VERSION 5.7 ;
  NOWIREEXTENSIONATPIN ON ;
  DIVIDERCHAR "/" ;
  BUSBITCHARS "[]" ;
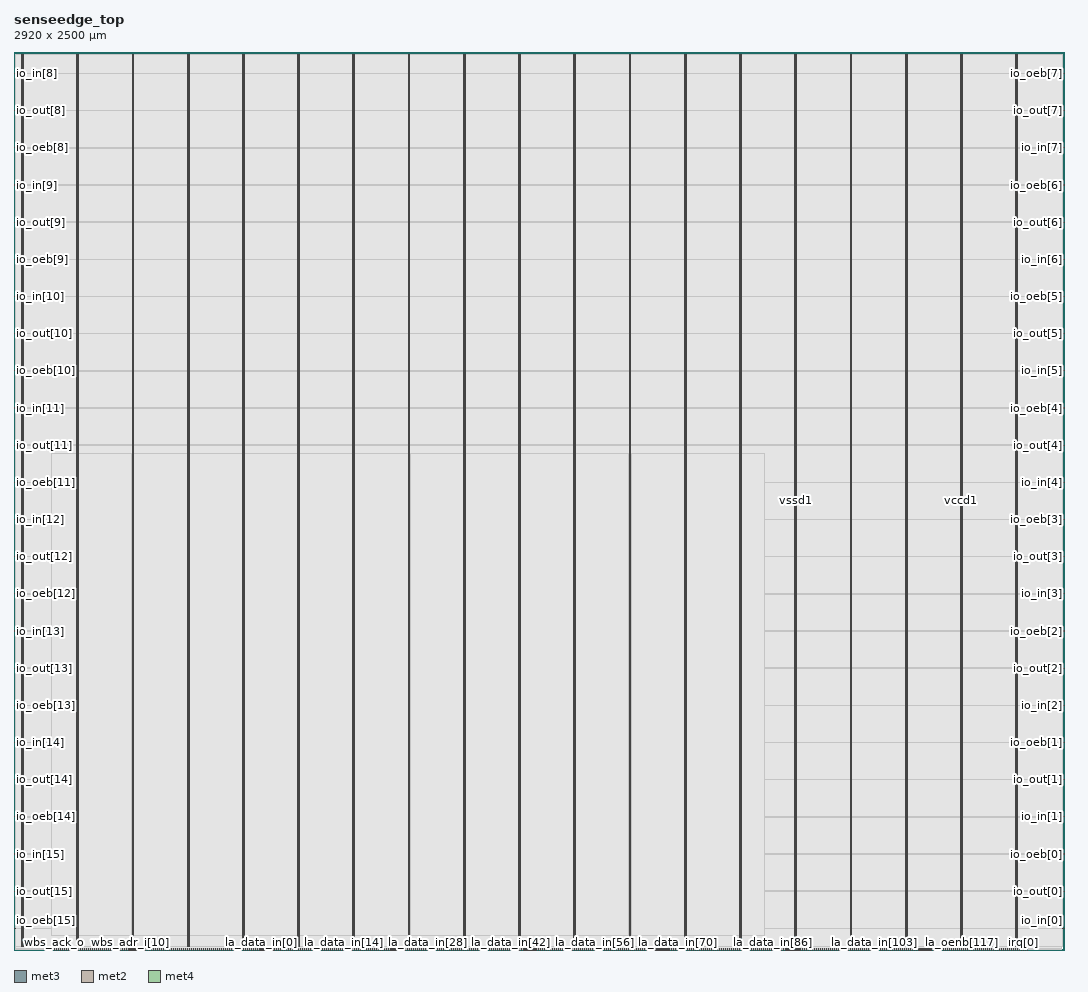
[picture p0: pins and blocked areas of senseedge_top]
MACRO senseedge_top
  CLASS BLOCK ;
  FOREIGN senseedge_top ;
  ORIGIN 0.000 0.000 ;
  SIZE 2920.000 BY 2500.000 ;
  PIN io_in[0]
    DIRECTION INPUT ;
    USE SIGNAL ;
    ANTENNAGATEAREA 1.424700 ;
    ANTENNADIFFAREA 0.434700 ;
    PORT
      LAYER met3 ;
        RECT 2916.000 59.880 2920.000 60.480 ;
    END
  END io_in[0]
  PIN io_in[10]
    DIRECTION INPUT ;
    USE SIGNAL ;
    PORT
      LAYER met3 ;
        RECT 0.000 1817.000 4.000 1817.600 ;
    END
  END io_in[10]
  PIN io_in[11]
    DIRECTION INPUT ;
    USE SIGNAL ;
    PORT
      LAYER met3 ;
        RECT 0.000 1506.920 4.000 1507.520 ;
    END
  END io_in[11]
  PIN io_in[12]
    DIRECTION INPUT ;
    USE SIGNAL ;
    PORT
      LAYER met3 ;
        RECT 0.000 1196.840 4.000 1197.440 ;
    END
  END io_in[12]
  PIN io_in[13]
    DIRECTION INPUT ;
    USE SIGNAL ;
    PORT
      LAYER met3 ;
        RECT 0.000 886.760 4.000 887.360 ;
    END
  END io_in[13]
  PIN io_in[14]
    DIRECTION INPUT ;
    USE SIGNAL ;
    PORT
      LAYER met3 ;
        RECT 0.000 576.680 4.000 577.280 ;
    END
  END io_in[14]
  PIN io_in[15]
    DIRECTION INPUT ;
    USE SIGNAL ;
    PORT
      LAYER met3 ;
        RECT 0.000 266.600 4.000 267.200 ;
    END
  END io_in[15]
  PIN io_in[1]
    DIRECTION INPUT ;
    USE SIGNAL ;
    PORT
      LAYER met3 ;
        RECT 2916.000 369.960 2920.000 370.560 ;
    END
  END io_in[1]
  PIN io_in[2]
    DIRECTION INPUT ;
    USE SIGNAL ;
    PORT
      LAYER met3 ;
        RECT 2916.000 680.040 2920.000 680.640 ;
    END
  END io_in[2]
  PIN io_in[3]
    DIRECTION INPUT ;
    USE SIGNAL ;
    PORT
      LAYER met3 ;
        RECT 2916.000 990.120 2920.000 990.720 ;
    END
  END io_in[3]
  PIN io_in[4]
    DIRECTION INPUT ;
    USE SIGNAL ;
    PORT
      LAYER met3 ;
        RECT 2916.000 1300.200 2920.000 1300.800 ;
    END
  END io_in[4]
  PIN io_in[5]
    DIRECTION INPUT ;
    USE SIGNAL ;
    PORT
      LAYER met3 ;
        RECT 2916.000 1610.280 2920.000 1610.880 ;
    END
  END io_in[5]
  PIN io_in[6]
    DIRECTION INPUT ;
    USE SIGNAL ;
    PORT
      LAYER met3 ;
        RECT 2916.000 1920.360 2920.000 1920.960 ;
    END
  END io_in[6]
  PIN io_in[7]
    DIRECTION INPUT ;
    USE SIGNAL ;
    PORT
      LAYER met3 ;
        RECT 2916.000 2230.440 2920.000 2231.040 ;
    END
  END io_in[7]
  PIN io_in[8]
    DIRECTION INPUT ;
    USE SIGNAL ;
    PORT
      LAYER met3 ;
        RECT 0.000 2437.160 4.000 2437.760 ;
    END
  END io_in[8]
  PIN io_in[9]
    DIRECTION INPUT ;
    USE SIGNAL ;
    PORT
      LAYER met3 ;
        RECT 0.000 2127.080 4.000 2127.680 ;
    END
  END io_in[9]
  PIN io_oeb[0]
    DIRECTION OUTPUT ;
    USE SIGNAL ;
    PORT
      LAYER met3 ;
        RECT 2916.000 266.600 2920.000 267.200 ;
    END
  END io_oeb[0]
  PIN io_oeb[10]
    DIRECTION OUTPUT ;
    USE SIGNAL ;
    PORT
      LAYER met3 ;
        RECT 0.000 1610.280 4.000 1610.880 ;
    END
  END io_oeb[10]
  PIN io_oeb[11]
    DIRECTION OUTPUT ;
    USE SIGNAL ;
    PORT
      LAYER met3 ;
        RECT 0.000 1300.200 4.000 1300.800 ;
    END
  END io_oeb[11]
  PIN io_oeb[12]
    DIRECTION OUTPUT ;
    USE SIGNAL ;
    PORT
      LAYER met3 ;
        RECT 0.000 990.120 4.000 990.720 ;
    END
  END io_oeb[12]
  PIN io_oeb[13]
    DIRECTION OUTPUT ;
    USE SIGNAL ;
    PORT
      LAYER met3 ;
        RECT 0.000 680.040 4.000 680.640 ;
    END
  END io_oeb[13]
  PIN io_oeb[14]
    DIRECTION OUTPUT ;
    USE SIGNAL ;
    PORT
      LAYER met3 ;
        RECT 0.000 369.960 4.000 370.560 ;
    END
  END io_oeb[14]
  PIN io_oeb[15]
    DIRECTION OUTPUT ;
    USE SIGNAL ;
    PORT
      LAYER met3 ;
        RECT 0.000 59.880 4.000 60.480 ;
    END
  END io_oeb[15]
  PIN io_oeb[1]
    DIRECTION OUTPUT ;
    USE SIGNAL ;
    PORT
      LAYER met3 ;
        RECT 2916.000 576.680 2920.000 577.280 ;
    END
  END io_oeb[1]
  PIN io_oeb[2]
    DIRECTION OUTPUT ;
    USE SIGNAL ;
    PORT
      LAYER met3 ;
        RECT 2916.000 886.760 2920.000 887.360 ;
    END
  END io_oeb[2]
  PIN io_oeb[3]
    DIRECTION OUTPUT ;
    USE SIGNAL ;
    PORT
      LAYER met3 ;
        RECT 2916.000 1196.840 2920.000 1197.440 ;
    END
  END io_oeb[3]
  PIN io_oeb[4]
    DIRECTION OUTPUT ;
    USE SIGNAL ;
    PORT
      LAYER met3 ;
        RECT 2916.000 1506.920 2920.000 1507.520 ;
    END
  END io_oeb[4]
  PIN io_oeb[5]
    DIRECTION OUTPUT ;
    USE SIGNAL ;
    PORT
      LAYER met3 ;
        RECT 2916.000 1817.000 2920.000 1817.600 ;
    END
  END io_oeb[5]
  PIN io_oeb[6]
    DIRECTION OUTPUT ;
    USE SIGNAL ;
    PORT
      LAYER met3 ;
        RECT 2916.000 2127.080 2920.000 2127.680 ;
    END
  END io_oeb[6]
  PIN io_oeb[7]
    DIRECTION OUTPUT ;
    USE SIGNAL ;
    PORT
      LAYER met3 ;
        RECT 2916.000 2437.160 2920.000 2437.760 ;
    END
  END io_oeb[7]
  PIN io_oeb[8]
    DIRECTION OUTPUT ;
    USE SIGNAL ;
    PORT
      LAYER met3 ;
        RECT 0.000 2230.440 4.000 2231.040 ;
    END
  END io_oeb[8]
  PIN io_oeb[9]
    DIRECTION OUTPUT ;
    USE SIGNAL ;
    PORT
      LAYER met3 ;
        RECT 0.000 1920.360 4.000 1920.960 ;
    END
  END io_oeb[9]
  PIN io_out[0]
    DIRECTION OUTPUT ;
    USE SIGNAL ;
    PORT
      LAYER met3 ;
        RECT 2916.000 163.240 2920.000 163.840 ;
    END
  END io_out[0]
  PIN io_out[10]
    DIRECTION OUTPUT ;
    USE SIGNAL ;
    PORT
      LAYER met3 ;
        RECT 0.000 1713.640 4.000 1714.240 ;
    END
  END io_out[10]
  PIN io_out[11]
    DIRECTION OUTPUT ;
    USE SIGNAL ;
    PORT
      LAYER met3 ;
        RECT 0.000 1403.560 4.000 1404.160 ;
    END
  END io_out[11]
  PIN io_out[12]
    DIRECTION OUTPUT ;
    USE SIGNAL ;
    PORT
      LAYER met3 ;
        RECT 0.000 1093.480 4.000 1094.080 ;
    END
  END io_out[12]
  PIN io_out[13]
    DIRECTION OUTPUT ;
    USE SIGNAL ;
    PORT
      LAYER met3 ;
        RECT 0.000 783.400 4.000 784.000 ;
    END
  END io_out[13]
  PIN io_out[14]
    DIRECTION OUTPUT ;
    USE SIGNAL ;
    PORT
      LAYER met3 ;
        RECT 0.000 473.320 4.000 473.920 ;
    END
  END io_out[14]
  PIN io_out[15]
    DIRECTION OUTPUT ;
    USE SIGNAL ;
    PORT
      LAYER met3 ;
        RECT 0.000 163.240 4.000 163.840 ;
    END
  END io_out[15]
  PIN io_out[1]
    DIRECTION OUTPUT ;
    USE SIGNAL ;
    ANTENNADIFFAREA 2.673000 ;
    PORT
      LAYER met3 ;
        RECT 2916.000 473.320 2920.000 473.920 ;
    END
  END io_out[1]
  PIN io_out[2]
    DIRECTION OUTPUT ;
    USE SIGNAL ;
    ANTENNADIFFAREA 2.673000 ;
    PORT
      LAYER met3 ;
        RECT 2916.000 783.400 2920.000 784.000 ;
    END
  END io_out[2]
  PIN io_out[3]
    DIRECTION OUTPUT ;
    USE SIGNAL ;
    ANTENNADIFFAREA 2.673000 ;
    PORT
      LAYER met3 ;
        RECT 2916.000 1093.480 2920.000 1094.080 ;
    END
  END io_out[3]
  PIN io_out[4]
    DIRECTION OUTPUT ;
    USE SIGNAL ;
    ANTENNADIFFAREA 2.673000 ;
    PORT
      LAYER met3 ;
        RECT 2916.000 1403.560 2920.000 1404.160 ;
    END
  END io_out[4]
  PIN io_out[5]
    DIRECTION OUTPUT ;
    USE SIGNAL ;
    PORT
      LAYER met3 ;
        RECT 2916.000 1713.640 2920.000 1714.240 ;
    END
  END io_out[5]
  PIN io_out[6]
    DIRECTION OUTPUT ;
    USE SIGNAL ;
    PORT
      LAYER met3 ;
        RECT 2916.000 2023.720 2920.000 2024.320 ;
    END
  END io_out[6]
  PIN io_out[7]
    DIRECTION OUTPUT ;
    USE SIGNAL ;
    PORT
      LAYER met3 ;
        RECT 2916.000 2333.800 2920.000 2334.400 ;
    END
  END io_out[7]
  PIN io_out[8]
    DIRECTION OUTPUT ;
    USE SIGNAL ;
    PORT
      LAYER met3 ;
        RECT 0.000 2333.800 4.000 2334.400 ;
    END
  END io_out[8]
  PIN io_out[9]
    DIRECTION OUTPUT ;
    USE SIGNAL ;
    PORT
      LAYER met3 ;
        RECT 0.000 2023.720 4.000 2024.320 ;
    END
  END io_out[9]
  PIN irq[0]
    DIRECTION OUTPUT ;
    USE SIGNAL ;
    ANTENNADIFFAREA 2.673000 ;
    PORT
      LAYER met2 ;
        RECT 2806.550 0.000 2806.830 4.000 ;
    END
  END irq[0]
  PIN irq[1]
    DIRECTION OUTPUT ;
    USE SIGNAL ;
    PORT
      LAYER met2 ;
        RECT 2812.070 0.000 2812.350 4.000 ;
    END
  END irq[1]
  PIN irq[2]
    DIRECTION OUTPUT ;
    USE SIGNAL ;
    PORT
      LAYER met2 ;
        RECT 2817.590 0.000 2817.870 4.000 ;
    END
  END irq[2]
  PIN la_data_in[0]
    DIRECTION INPUT ;
    USE SIGNAL ;
    PORT
      LAYER met2 ;
        RECT 686.870 0.000 687.150 4.000 ;
    END
  END la_data_in[0]
  PIN la_data_in[100]
    DIRECTION INPUT ;
    USE SIGNAL ;
    PORT
      LAYER met2 ;
        RECT 2342.870 0.000 2343.150 4.000 ;
    END
  END la_data_in[100]
  PIN la_data_in[101]
    DIRECTION INPUT ;
    USE SIGNAL ;
    PORT
      LAYER met2 ;
        RECT 2359.430 0.000 2359.710 4.000 ;
    END
  END la_data_in[101]
  PIN la_data_in[102]
    DIRECTION INPUT ;
    USE SIGNAL ;
    PORT
      LAYER met2 ;
        RECT 2375.990 0.000 2376.270 4.000 ;
    END
  END la_data_in[102]
  PIN la_data_in[103]
    DIRECTION INPUT ;
    USE SIGNAL ;
    PORT
      LAYER met2 ;
        RECT 2392.550 0.000 2392.830 4.000 ;
    END
  END la_data_in[103]
  PIN la_data_in[104]
    DIRECTION INPUT ;
    USE SIGNAL ;
    PORT
      LAYER met2 ;
        RECT 2409.110 0.000 2409.390 4.000 ;
    END
  END la_data_in[104]
  PIN la_data_in[105]
    DIRECTION INPUT ;
    USE SIGNAL ;
    PORT
      LAYER met2 ;
        RECT 2425.670 0.000 2425.950 4.000 ;
    END
  END la_data_in[105]
  PIN la_data_in[106]
    DIRECTION INPUT ;
    USE SIGNAL ;
    PORT
      LAYER met2 ;
        RECT 2442.230 0.000 2442.510 4.000 ;
    END
  END la_data_in[106]
  PIN la_data_in[107]
    DIRECTION INPUT ;
    USE SIGNAL ;
    PORT
      LAYER met2 ;
        RECT 2458.790 0.000 2459.070 4.000 ;
    END
  END la_data_in[107]
  PIN la_data_in[108]
    DIRECTION INPUT ;
    USE SIGNAL ;
    PORT
      LAYER met2 ;
        RECT 2475.350 0.000 2475.630 4.000 ;
    END
  END la_data_in[108]
  PIN la_data_in[109]
    DIRECTION INPUT ;
    USE SIGNAL ;
    PORT
      LAYER met2 ;
        RECT 2491.910 0.000 2492.190 4.000 ;
    END
  END la_data_in[109]
  PIN la_data_in[10]
    DIRECTION INPUT ;
    USE SIGNAL ;
    PORT
      LAYER met2 ;
        RECT 852.470 0.000 852.750 4.000 ;
    END
  END la_data_in[10]
  PIN la_data_in[110]
    DIRECTION INPUT ;
    USE SIGNAL ;
    PORT
      LAYER met2 ;
        RECT 2508.470 0.000 2508.750 4.000 ;
    END
  END la_data_in[110]
  PIN la_data_in[111]
    DIRECTION INPUT ;
    USE SIGNAL ;
    PORT
      LAYER met2 ;
        RECT 2525.030 0.000 2525.310 4.000 ;
    END
  END la_data_in[111]
  PIN la_data_in[112]
    DIRECTION INPUT ;
    USE SIGNAL ;
    PORT
      LAYER met2 ;
        RECT 2541.590 0.000 2541.870 4.000 ;
    END
  END la_data_in[112]
  PIN la_data_in[113]
    DIRECTION INPUT ;
    USE SIGNAL ;
    PORT
      LAYER met2 ;
        RECT 2558.150 0.000 2558.430 4.000 ;
    END
  END la_data_in[113]
  PIN la_data_in[114]
    DIRECTION INPUT ;
    USE SIGNAL ;
    PORT
      LAYER met2 ;
        RECT 2574.710 0.000 2574.990 4.000 ;
    END
  END la_data_in[114]
  PIN la_data_in[115]
    DIRECTION INPUT ;
    USE SIGNAL ;
    PORT
      LAYER met2 ;
        RECT 2591.270 0.000 2591.550 4.000 ;
    END
  END la_data_in[115]
  PIN la_data_in[116]
    DIRECTION INPUT ;
    USE SIGNAL ;
    PORT
      LAYER met2 ;
        RECT 2607.830 0.000 2608.110 4.000 ;
    END
  END la_data_in[116]
  PIN la_data_in[117]
    DIRECTION INPUT ;
    USE SIGNAL ;
    PORT
      LAYER met2 ;
        RECT 2624.390 0.000 2624.670 4.000 ;
    END
  END la_data_in[117]
  PIN la_data_in[118]
    DIRECTION INPUT ;
    USE SIGNAL ;
    PORT
      LAYER met2 ;
        RECT 2640.950 0.000 2641.230 4.000 ;
    END
  END la_data_in[118]
  PIN la_data_in[119]
    DIRECTION INPUT ;
    USE SIGNAL ;
    PORT
      LAYER met2 ;
        RECT 2657.510 0.000 2657.790 4.000 ;
    END
  END la_data_in[119]
  PIN la_data_in[11]
    DIRECTION INPUT ;
    USE SIGNAL ;
    PORT
      LAYER met2 ;
        RECT 869.030 0.000 869.310 4.000 ;
    END
  END la_data_in[11]
  PIN la_data_in[120]
    DIRECTION INPUT ;
    USE SIGNAL ;
    PORT
      LAYER met2 ;
        RECT 2674.070 0.000 2674.350 4.000 ;
    END
  END la_data_in[120]
  PIN la_data_in[121]
    DIRECTION INPUT ;
    USE SIGNAL ;
    PORT
      LAYER met2 ;
        RECT 2690.630 0.000 2690.910 4.000 ;
    END
  END la_data_in[121]
  PIN la_data_in[122]
    DIRECTION INPUT ;
    USE SIGNAL ;
    PORT
      LAYER met2 ;
        RECT 2707.190 0.000 2707.470 4.000 ;
    END
  END la_data_in[122]
  PIN la_data_in[123]
    DIRECTION INPUT ;
    USE SIGNAL ;
    PORT
      LAYER met2 ;
        RECT 2723.750 0.000 2724.030 4.000 ;
    END
  END la_data_in[123]
  PIN la_data_in[124]
    DIRECTION INPUT ;
    USE SIGNAL ;
    PORT
      LAYER met2 ;
        RECT 2740.310 0.000 2740.590 4.000 ;
    END
  END la_data_in[124]
  PIN la_data_in[125]
    DIRECTION INPUT ;
    USE SIGNAL ;
    PORT
      LAYER met2 ;
        RECT 2756.870 0.000 2757.150 4.000 ;
    END
  END la_data_in[125]
  PIN la_data_in[126]
    DIRECTION INPUT ;
    USE SIGNAL ;
    PORT
      LAYER met2 ;
        RECT 2773.430 0.000 2773.710 4.000 ;
    END
  END la_data_in[126]
  PIN la_data_in[127]
    DIRECTION INPUT ;
    USE SIGNAL ;
    PORT
      LAYER met2 ;
        RECT 2789.990 0.000 2790.270 4.000 ;
    END
  END la_data_in[127]
  PIN la_data_in[12]
    DIRECTION INPUT ;
    USE SIGNAL ;
    PORT
      LAYER met2 ;
        RECT 885.590 0.000 885.870 4.000 ;
    END
  END la_data_in[12]
  PIN la_data_in[13]
    DIRECTION INPUT ;
    USE SIGNAL ;
    PORT
      LAYER met2 ;
        RECT 902.150 0.000 902.430 4.000 ;
    END
  END la_data_in[13]
  PIN la_data_in[14]
    DIRECTION INPUT ;
    USE SIGNAL ;
    PORT
      LAYER met2 ;
        RECT 918.710 0.000 918.990 4.000 ;
    END
  END la_data_in[14]
  PIN la_data_in[15]
    DIRECTION INPUT ;
    USE SIGNAL ;
    PORT
      LAYER met2 ;
        RECT 935.270 0.000 935.550 4.000 ;
    END
  END la_data_in[15]
  PIN la_data_in[16]
    DIRECTION INPUT ;
    USE SIGNAL ;
    PORT
      LAYER met2 ;
        RECT 951.830 0.000 952.110 4.000 ;
    END
  END la_data_in[16]
  PIN la_data_in[17]
    DIRECTION INPUT ;
    USE SIGNAL ;
    PORT
      LAYER met2 ;
        RECT 968.390 0.000 968.670 4.000 ;
    END
  END la_data_in[17]
  PIN la_data_in[18]
    DIRECTION INPUT ;
    USE SIGNAL ;
    PORT
      LAYER met2 ;
        RECT 984.950 0.000 985.230 4.000 ;
    END
  END la_data_in[18]
  PIN la_data_in[19]
    DIRECTION INPUT ;
    USE SIGNAL ;
    PORT
      LAYER met2 ;
        RECT 1001.510 0.000 1001.790 4.000 ;
    END
  END la_data_in[19]
  PIN la_data_in[1]
    DIRECTION INPUT ;
    USE SIGNAL ;
    PORT
      LAYER met2 ;
        RECT 703.430 0.000 703.710 4.000 ;
    END
  END la_data_in[1]
  PIN la_data_in[20]
    DIRECTION INPUT ;
    USE SIGNAL ;
    PORT
      LAYER met2 ;
        RECT 1018.070 0.000 1018.350 4.000 ;
    END
  END la_data_in[20]
  PIN la_data_in[21]
    DIRECTION INPUT ;
    USE SIGNAL ;
    PORT
      LAYER met2 ;
        RECT 1034.630 0.000 1034.910 4.000 ;
    END
  END la_data_in[21]
  PIN la_data_in[22]
    DIRECTION INPUT ;
    USE SIGNAL ;
    PORT
      LAYER met2 ;
        RECT 1051.190 0.000 1051.470 4.000 ;
    END
  END la_data_in[22]
  PIN la_data_in[23]
    DIRECTION INPUT ;
    USE SIGNAL ;
    PORT
      LAYER met2 ;
        RECT 1067.750 0.000 1068.030 4.000 ;
    END
  END la_data_in[23]
  PIN la_data_in[24]
    DIRECTION INPUT ;
    USE SIGNAL ;
    PORT
      LAYER met2 ;
        RECT 1084.310 0.000 1084.590 4.000 ;
    END
  END la_data_in[24]
  PIN la_data_in[25]
    DIRECTION INPUT ;
    USE SIGNAL ;
    PORT
      LAYER met2 ;
        RECT 1100.870 0.000 1101.150 4.000 ;
    END
  END la_data_in[25]
  PIN la_data_in[26]
    DIRECTION INPUT ;
    USE SIGNAL ;
    PORT
      LAYER met2 ;
        RECT 1117.430 0.000 1117.710 4.000 ;
    END
  END la_data_in[26]
  PIN la_data_in[27]
    DIRECTION INPUT ;
    USE SIGNAL ;
    PORT
      LAYER met2 ;
        RECT 1133.990 0.000 1134.270 4.000 ;
    END
  END la_data_in[27]
  PIN la_data_in[28]
    DIRECTION INPUT ;
    USE SIGNAL ;
    PORT
      LAYER met2 ;
        RECT 1150.550 0.000 1150.830 4.000 ;
    END
  END la_data_in[28]
  PIN la_data_in[29]
    DIRECTION INPUT ;
    USE SIGNAL ;
    PORT
      LAYER met2 ;
        RECT 1167.110 0.000 1167.390 4.000 ;
    END
  END la_data_in[29]
  PIN la_data_in[2]
    DIRECTION INPUT ;
    USE SIGNAL ;
    PORT
      LAYER met2 ;
        RECT 719.990 0.000 720.270 4.000 ;
    END
  END la_data_in[2]
  PIN la_data_in[30]
    DIRECTION INPUT ;
    USE SIGNAL ;
    PORT
      LAYER met2 ;
        RECT 1183.670 0.000 1183.950 4.000 ;
    END
  END la_data_in[30]
  PIN la_data_in[31]
    DIRECTION INPUT ;
    USE SIGNAL ;
    PORT
      LAYER met2 ;
        RECT 1200.230 0.000 1200.510 4.000 ;
    END
  END la_data_in[31]
  PIN la_data_in[32]
    DIRECTION INPUT ;
    USE SIGNAL ;
    PORT
      LAYER met2 ;
        RECT 1216.790 0.000 1217.070 4.000 ;
    END
  END la_data_in[32]
  PIN la_data_in[33]
    DIRECTION INPUT ;
    USE SIGNAL ;
    PORT
      LAYER met2 ;
        RECT 1233.350 0.000 1233.630 4.000 ;
    END
  END la_data_in[33]
  PIN la_data_in[34]
    DIRECTION INPUT ;
    USE SIGNAL ;
    PORT
      LAYER met2 ;
        RECT 1249.910 0.000 1250.190 4.000 ;
    END
  END la_data_in[34]
  PIN la_data_in[35]
    DIRECTION INPUT ;
    USE SIGNAL ;
    PORT
      LAYER met2 ;
        RECT 1266.470 0.000 1266.750 4.000 ;
    END
  END la_data_in[35]
  PIN la_data_in[36]
    DIRECTION INPUT ;
    USE SIGNAL ;
    PORT
      LAYER met2 ;
        RECT 1283.030 0.000 1283.310 4.000 ;
    END
  END la_data_in[36]
  PIN la_data_in[37]
    DIRECTION INPUT ;
    USE SIGNAL ;
    PORT
      LAYER met2 ;
        RECT 1299.590 0.000 1299.870 4.000 ;
    END
  END la_data_in[37]
  PIN la_data_in[38]
    DIRECTION INPUT ;
    USE SIGNAL ;
    PORT
      LAYER met2 ;
        RECT 1316.150 0.000 1316.430 4.000 ;
    END
  END la_data_in[38]
  PIN la_data_in[39]
    DIRECTION INPUT ;
    USE SIGNAL ;
    PORT
      LAYER met2 ;
        RECT 1332.710 0.000 1332.990 4.000 ;
    END
  END la_data_in[39]
  PIN la_data_in[3]
    DIRECTION INPUT ;
    USE SIGNAL ;
    PORT
      LAYER met2 ;
        RECT 736.550 0.000 736.830 4.000 ;
    END
  END la_data_in[3]
  PIN la_data_in[40]
    DIRECTION INPUT ;
    USE SIGNAL ;
    PORT
      LAYER met2 ;
        RECT 1349.270 0.000 1349.550 4.000 ;
    END
  END la_data_in[40]
  PIN la_data_in[41]
    DIRECTION INPUT ;
    USE SIGNAL ;
    PORT
      LAYER met2 ;
        RECT 1365.830 0.000 1366.110 4.000 ;
    END
  END la_data_in[41]
  PIN la_data_in[42]
    DIRECTION INPUT ;
    USE SIGNAL ;
    PORT
      LAYER met2 ;
        RECT 1382.390 0.000 1382.670 4.000 ;
    END
  END la_data_in[42]
  PIN la_data_in[43]
    DIRECTION INPUT ;
    USE SIGNAL ;
    PORT
      LAYER met2 ;
        RECT 1398.950 0.000 1399.230 4.000 ;
    END
  END la_data_in[43]
  PIN la_data_in[44]
    DIRECTION INPUT ;
    USE SIGNAL ;
    PORT
      LAYER met2 ;
        RECT 1415.510 0.000 1415.790 4.000 ;
    END
  END la_data_in[44]
  PIN la_data_in[45]
    DIRECTION INPUT ;
    USE SIGNAL ;
    PORT
      LAYER met2 ;
        RECT 1432.070 0.000 1432.350 4.000 ;
    END
  END la_data_in[45]
  PIN la_data_in[46]
    DIRECTION INPUT ;
    USE SIGNAL ;
    PORT
      LAYER met2 ;
        RECT 1448.630 0.000 1448.910 4.000 ;
    END
  END la_data_in[46]
  PIN la_data_in[47]
    DIRECTION INPUT ;
    USE SIGNAL ;
    PORT
      LAYER met2 ;
        RECT 1465.190 0.000 1465.470 4.000 ;
    END
  END la_data_in[47]
  PIN la_data_in[48]
    DIRECTION INPUT ;
    USE SIGNAL ;
    PORT
      LAYER met2 ;
        RECT 1481.750 0.000 1482.030 4.000 ;
    END
  END la_data_in[48]
  PIN la_data_in[49]
    DIRECTION INPUT ;
    USE SIGNAL ;
    PORT
      LAYER met2 ;
        RECT 1498.310 0.000 1498.590 4.000 ;
    END
  END la_data_in[49]
  PIN la_data_in[4]
    DIRECTION INPUT ;
    USE SIGNAL ;
    PORT
      LAYER met2 ;
        RECT 753.110 0.000 753.390 4.000 ;
    END
  END la_data_in[4]
  PIN la_data_in[50]
    DIRECTION INPUT ;
    USE SIGNAL ;
    PORT
      LAYER met2 ;
        RECT 1514.870 0.000 1515.150 4.000 ;
    END
  END la_data_in[50]
  PIN la_data_in[51]
    DIRECTION INPUT ;
    USE SIGNAL ;
    PORT
      LAYER met2 ;
        RECT 1531.430 0.000 1531.710 4.000 ;
    END
  END la_data_in[51]
  PIN la_data_in[52]
    DIRECTION INPUT ;
    USE SIGNAL ;
    PORT
      LAYER met2 ;
        RECT 1547.990 0.000 1548.270 4.000 ;
    END
  END la_data_in[52]
  PIN la_data_in[53]
    DIRECTION INPUT ;
    USE SIGNAL ;
    PORT
      LAYER met2 ;
        RECT 1564.550 0.000 1564.830 4.000 ;
    END
  END la_data_in[53]
  PIN la_data_in[54]
    DIRECTION INPUT ;
    USE SIGNAL ;
    PORT
      LAYER met2 ;
        RECT 1581.110 0.000 1581.390 4.000 ;
    END
  END la_data_in[54]
  PIN la_data_in[55]
    DIRECTION INPUT ;
    USE SIGNAL ;
    PORT
      LAYER met2 ;
        RECT 1597.670 0.000 1597.950 4.000 ;
    END
  END la_data_in[55]
  PIN la_data_in[56]
    DIRECTION INPUT ;
    USE SIGNAL ;
    PORT
      LAYER met2 ;
        RECT 1614.230 0.000 1614.510 4.000 ;
    END
  END la_data_in[56]
  PIN la_data_in[57]
    DIRECTION INPUT ;
    USE SIGNAL ;
    PORT
      LAYER met2 ;
        RECT 1630.790 0.000 1631.070 4.000 ;
    END
  END la_data_in[57]
  PIN la_data_in[58]
    DIRECTION INPUT ;
    USE SIGNAL ;
    PORT
      LAYER met2 ;
        RECT 1647.350 0.000 1647.630 4.000 ;
    END
  END la_data_in[58]
  PIN la_data_in[59]
    DIRECTION INPUT ;
    USE SIGNAL ;
    PORT
      LAYER met2 ;
        RECT 1663.910 0.000 1664.190 4.000 ;
    END
  END la_data_in[59]
  PIN la_data_in[5]
    DIRECTION INPUT ;
    USE SIGNAL ;
    PORT
      LAYER met2 ;
        RECT 769.670 0.000 769.950 4.000 ;
    END
  END la_data_in[5]
  PIN la_data_in[60]
    DIRECTION INPUT ;
    USE SIGNAL ;
    PORT
      LAYER met2 ;
        RECT 1680.470 0.000 1680.750 4.000 ;
    END
  END la_data_in[60]
  PIN la_data_in[61]
    DIRECTION INPUT ;
    USE SIGNAL ;
    PORT
      LAYER met2 ;
        RECT 1697.030 0.000 1697.310 4.000 ;
    END
  END la_data_in[61]
  PIN la_data_in[62]
    DIRECTION INPUT ;
    USE SIGNAL ;
    PORT
      LAYER met2 ;
        RECT 1713.590 0.000 1713.870 4.000 ;
    END
  END la_data_in[62]
  PIN la_data_in[63]
    DIRECTION INPUT ;
    USE SIGNAL ;
    PORT
      LAYER met2 ;
        RECT 1730.150 0.000 1730.430 4.000 ;
    END
  END la_data_in[63]
  PIN la_data_in[64]
    DIRECTION INPUT ;
    USE SIGNAL ;
    PORT
      LAYER met2 ;
        RECT 1746.710 0.000 1746.990 4.000 ;
    END
  END la_data_in[64]
  PIN la_data_in[65]
    DIRECTION INPUT ;
    USE SIGNAL ;
    PORT
      LAYER met2 ;
        RECT 1763.270 0.000 1763.550 4.000 ;
    END
  END la_data_in[65]
  PIN la_data_in[66]
    DIRECTION INPUT ;
    USE SIGNAL ;
    PORT
      LAYER met2 ;
        RECT 1779.830 0.000 1780.110 4.000 ;
    END
  END la_data_in[66]
  PIN la_data_in[67]
    DIRECTION INPUT ;
    USE SIGNAL ;
    PORT
      LAYER met2 ;
        RECT 1796.390 0.000 1796.670 4.000 ;
    END
  END la_data_in[67]
  PIN la_data_in[68]
    DIRECTION INPUT ;
    USE SIGNAL ;
    PORT
      LAYER met2 ;
        RECT 1812.950 0.000 1813.230 4.000 ;
    END
  END la_data_in[68]
  PIN la_data_in[69]
    DIRECTION INPUT ;
    USE SIGNAL ;
    PORT
      LAYER met2 ;
        RECT 1829.510 0.000 1829.790 4.000 ;
    END
  END la_data_in[69]
  PIN la_data_in[6]
    DIRECTION INPUT ;
    USE SIGNAL ;
    PORT
      LAYER met2 ;
        RECT 786.230 0.000 786.510 4.000 ;
    END
  END la_data_in[6]
  PIN la_data_in[70]
    DIRECTION INPUT ;
    USE SIGNAL ;
    PORT
      LAYER met2 ;
        RECT 1846.070 0.000 1846.350 4.000 ;
    END
  END la_data_in[70]
  PIN la_data_in[71]
    DIRECTION INPUT ;
    USE SIGNAL ;
    PORT
      LAYER met2 ;
        RECT 1862.630 0.000 1862.910 4.000 ;
    END
  END la_data_in[71]
  PIN la_data_in[72]
    DIRECTION INPUT ;
    USE SIGNAL ;
    PORT
      LAYER met2 ;
        RECT 1879.190 0.000 1879.470 4.000 ;
    END
  END la_data_in[72]
  PIN la_data_in[73]
    DIRECTION INPUT ;
    USE SIGNAL ;
    PORT
      LAYER met2 ;
        RECT 1895.750 0.000 1896.030 4.000 ;
    END
  END la_data_in[73]
  PIN la_data_in[74]
    DIRECTION INPUT ;
    USE SIGNAL ;
    PORT
      LAYER met2 ;
        RECT 1912.310 0.000 1912.590 4.000 ;
    END
  END la_data_in[74]
  PIN la_data_in[75]
    DIRECTION INPUT ;
    USE SIGNAL ;
    PORT
      LAYER met2 ;
        RECT 1928.870 0.000 1929.150 4.000 ;
    END
  END la_data_in[75]
  PIN la_data_in[76]
    DIRECTION INPUT ;
    USE SIGNAL ;
    PORT
      LAYER met2 ;
        RECT 1945.430 0.000 1945.710 4.000 ;
    END
  END la_data_in[76]
  PIN la_data_in[77]
    DIRECTION INPUT ;
    USE SIGNAL ;
    PORT
      LAYER met2 ;
        RECT 1961.990 0.000 1962.270 4.000 ;
    END
  END la_data_in[77]
  PIN la_data_in[78]
    DIRECTION INPUT ;
    USE SIGNAL ;
    PORT
      LAYER met2 ;
        RECT 1978.550 0.000 1978.830 4.000 ;
    END
  END la_data_in[78]
  PIN la_data_in[79]
    DIRECTION INPUT ;
    USE SIGNAL ;
    PORT
      LAYER met2 ;
        RECT 1995.110 0.000 1995.390 4.000 ;
    END
  END la_data_in[79]
  PIN la_data_in[7]
    DIRECTION INPUT ;
    USE SIGNAL ;
    PORT
      LAYER met2 ;
        RECT 802.790 0.000 803.070 4.000 ;
    END
  END la_data_in[7]
  PIN la_data_in[80]
    DIRECTION INPUT ;
    USE SIGNAL ;
    PORT
      LAYER met2 ;
        RECT 2011.670 0.000 2011.950 4.000 ;
    END
  END la_data_in[80]
  PIN la_data_in[81]
    DIRECTION INPUT ;
    USE SIGNAL ;
    PORT
      LAYER met2 ;
        RECT 2028.230 0.000 2028.510 4.000 ;
    END
  END la_data_in[81]
  PIN la_data_in[82]
    DIRECTION INPUT ;
    USE SIGNAL ;
    PORT
      LAYER met2 ;
        RECT 2044.790 0.000 2045.070 4.000 ;
    END
  END la_data_in[82]
  PIN la_data_in[83]
    DIRECTION INPUT ;
    USE SIGNAL ;
    PORT
      LAYER met2 ;
        RECT 2061.350 0.000 2061.630 4.000 ;
    END
  END la_data_in[83]
  PIN la_data_in[84]
    DIRECTION INPUT ;
    USE SIGNAL ;
    PORT
      LAYER met2 ;
        RECT 2077.910 0.000 2078.190 4.000 ;
    END
  END la_data_in[84]
  PIN la_data_in[85]
    DIRECTION INPUT ;
    USE SIGNAL ;
    PORT
      LAYER met2 ;
        RECT 2094.470 0.000 2094.750 4.000 ;
    END
  END la_data_in[85]
  PIN la_data_in[86]
    DIRECTION INPUT ;
    USE SIGNAL ;
    PORT
      LAYER met2 ;
        RECT 2111.030 0.000 2111.310 4.000 ;
    END
  END la_data_in[86]
  PIN la_data_in[87]
    DIRECTION INPUT ;
    USE SIGNAL ;
    PORT
      LAYER met2 ;
        RECT 2127.590 0.000 2127.870 4.000 ;
    END
  END la_data_in[87]
  PIN la_data_in[88]
    DIRECTION INPUT ;
    USE SIGNAL ;
    PORT
      LAYER met2 ;
        RECT 2144.150 0.000 2144.430 4.000 ;
    END
  END la_data_in[88]
  PIN la_data_in[89]
    DIRECTION INPUT ;
    USE SIGNAL ;
    PORT
      LAYER met2 ;
        RECT 2160.710 0.000 2160.990 4.000 ;
    END
  END la_data_in[89]
  PIN la_data_in[8]
    DIRECTION INPUT ;
    USE SIGNAL ;
    PORT
      LAYER met2 ;
        RECT 819.350 0.000 819.630 4.000 ;
    END
  END la_data_in[8]
  PIN la_data_in[90]
    DIRECTION INPUT ;
    USE SIGNAL ;
    PORT
      LAYER met2 ;
        RECT 2177.270 0.000 2177.550 4.000 ;
    END
  END la_data_in[90]
  PIN la_data_in[91]
    DIRECTION INPUT ;
    USE SIGNAL ;
    PORT
      LAYER met2 ;
        RECT 2193.830 0.000 2194.110 4.000 ;
    END
  END la_data_in[91]
  PIN la_data_in[92]
    DIRECTION INPUT ;
    USE SIGNAL ;
    PORT
      LAYER met2 ;
        RECT 2210.390 0.000 2210.670 4.000 ;
    END
  END la_data_in[92]
  PIN la_data_in[93]
    DIRECTION INPUT ;
    USE SIGNAL ;
    PORT
      LAYER met2 ;
        RECT 2226.950 0.000 2227.230 4.000 ;
    END
  END la_data_in[93]
  PIN la_data_in[94]
    DIRECTION INPUT ;
    USE SIGNAL ;
    PORT
      LAYER met2 ;
        RECT 2243.510 0.000 2243.790 4.000 ;
    END
  END la_data_in[94]
  PIN la_data_in[95]
    DIRECTION INPUT ;
    USE SIGNAL ;
    PORT
      LAYER met2 ;
        RECT 2260.070 0.000 2260.350 4.000 ;
    END
  END la_data_in[95]
  PIN la_data_in[96]
    DIRECTION INPUT ;
    USE SIGNAL ;
    PORT
      LAYER met2 ;
        RECT 2276.630 0.000 2276.910 4.000 ;
    END
  END la_data_in[96]
  PIN la_data_in[97]
    DIRECTION INPUT ;
    USE SIGNAL ;
    PORT
      LAYER met2 ;
        RECT 2293.190 0.000 2293.470 4.000 ;
    END
  END la_data_in[97]
  PIN la_data_in[98]
    DIRECTION INPUT ;
    USE SIGNAL ;
    PORT
      LAYER met2 ;
        RECT 2309.750 0.000 2310.030 4.000 ;
    END
  END la_data_in[98]
  PIN la_data_in[99]
    DIRECTION INPUT ;
    USE SIGNAL ;
    PORT
      LAYER met2 ;
        RECT 2326.310 0.000 2326.590 4.000 ;
    END
  END la_data_in[99]
  PIN la_data_in[9]
    DIRECTION INPUT ;
    USE SIGNAL ;
    PORT
      LAYER met2 ;
        RECT 835.910 0.000 836.190 4.000 ;
    END
  END la_data_in[9]
  PIN la_data_out[0]
    DIRECTION OUTPUT ;
    USE SIGNAL ;
    ANTENNADIFFAREA 2.673000 ;
    PORT
      LAYER met2 ;
        RECT 692.390 0.000 692.670 4.000 ;
    END
  END la_data_out[0]
  PIN la_data_out[100]
    DIRECTION OUTPUT ;
    USE SIGNAL ;
    PORT
      LAYER met2 ;
        RECT 2348.390 0.000 2348.670 4.000 ;
    END
  END la_data_out[100]
  PIN la_data_out[101]
    DIRECTION OUTPUT ;
    USE SIGNAL ;
    PORT
      LAYER met2 ;
        RECT 2364.950 0.000 2365.230 4.000 ;
    END
  END la_data_out[101]
  PIN la_data_out[102]
    DIRECTION OUTPUT ;
    USE SIGNAL ;
    PORT
      LAYER met2 ;
        RECT 2381.510 0.000 2381.790 4.000 ;
    END
  END la_data_out[102]
  PIN la_data_out[103]
    DIRECTION OUTPUT ;
    USE SIGNAL ;
    PORT
      LAYER met2 ;
        RECT 2398.070 0.000 2398.350 4.000 ;
    END
  END la_data_out[103]
  PIN la_data_out[104]
    DIRECTION OUTPUT ;
    USE SIGNAL ;
    PORT
      LAYER met2 ;
        RECT 2414.630 0.000 2414.910 4.000 ;
    END
  END la_data_out[104]
  PIN la_data_out[105]
    DIRECTION OUTPUT ;
    USE SIGNAL ;
    PORT
      LAYER met2 ;
        RECT 2431.190 0.000 2431.470 4.000 ;
    END
  END la_data_out[105]
  PIN la_data_out[106]
    DIRECTION OUTPUT ;
    USE SIGNAL ;
    PORT
      LAYER met2 ;
        RECT 2447.750 0.000 2448.030 4.000 ;
    END
  END la_data_out[106]
  PIN la_data_out[107]
    DIRECTION OUTPUT ;
    USE SIGNAL ;
    PORT
      LAYER met2 ;
        RECT 2464.310 0.000 2464.590 4.000 ;
    END
  END la_data_out[107]
  PIN la_data_out[108]
    DIRECTION OUTPUT ;
    USE SIGNAL ;
    PORT
      LAYER met2 ;
        RECT 2480.870 0.000 2481.150 4.000 ;
    END
  END la_data_out[108]
  PIN la_data_out[109]
    DIRECTION OUTPUT ;
    USE SIGNAL ;
    PORT
      LAYER met2 ;
        RECT 2497.430 0.000 2497.710 4.000 ;
    END
  END la_data_out[109]
  PIN la_data_out[10]
    DIRECTION OUTPUT ;
    USE SIGNAL ;
    ANTENNADIFFAREA 2.673000 ;
    PORT
      LAYER met2 ;
        RECT 857.990 0.000 858.270 4.000 ;
    END
  END la_data_out[10]
  PIN la_data_out[110]
    DIRECTION OUTPUT ;
    USE SIGNAL ;
    PORT
      LAYER met2 ;
        RECT 2513.990 0.000 2514.270 4.000 ;
    END
  END la_data_out[110]
  PIN la_data_out[111]
    DIRECTION OUTPUT ;
    USE SIGNAL ;
    PORT
      LAYER met2 ;
        RECT 2530.550 0.000 2530.830 4.000 ;
    END
  END la_data_out[111]
  PIN la_data_out[112]
    DIRECTION OUTPUT ;
    USE SIGNAL ;
    PORT
      LAYER met2 ;
        RECT 2547.110 0.000 2547.390 4.000 ;
    END
  END la_data_out[112]
  PIN la_data_out[113]
    DIRECTION OUTPUT ;
    USE SIGNAL ;
    PORT
      LAYER met2 ;
        RECT 2563.670 0.000 2563.950 4.000 ;
    END
  END la_data_out[113]
  PIN la_data_out[114]
    DIRECTION OUTPUT ;
    USE SIGNAL ;
    PORT
      LAYER met2 ;
        RECT 2580.230 0.000 2580.510 4.000 ;
    END
  END la_data_out[114]
  PIN la_data_out[115]
    DIRECTION OUTPUT ;
    USE SIGNAL ;
    PORT
      LAYER met2 ;
        RECT 2596.790 0.000 2597.070 4.000 ;
    END
  END la_data_out[115]
  PIN la_data_out[116]
    DIRECTION OUTPUT ;
    USE SIGNAL ;
    PORT
      LAYER met2 ;
        RECT 2613.350 0.000 2613.630 4.000 ;
    END
  END la_data_out[116]
  PIN la_data_out[117]
    DIRECTION OUTPUT ;
    USE SIGNAL ;
    PORT
      LAYER met2 ;
        RECT 2629.910 0.000 2630.190 4.000 ;
    END
  END la_data_out[117]
  PIN la_data_out[118]
    DIRECTION OUTPUT ;
    USE SIGNAL ;
    PORT
      LAYER met2 ;
        RECT 2646.470 0.000 2646.750 4.000 ;
    END
  END la_data_out[118]
  PIN la_data_out[119]
    DIRECTION OUTPUT ;
    USE SIGNAL ;
    PORT
      LAYER met2 ;
        RECT 2663.030 0.000 2663.310 4.000 ;
    END
  END la_data_out[119]
  PIN la_data_out[11]
    DIRECTION OUTPUT ;
    USE SIGNAL ;
    ANTENNADIFFAREA 2.673000 ;
    PORT
      LAYER met2 ;
        RECT 874.550 0.000 874.830 4.000 ;
    END
  END la_data_out[11]
  PIN la_data_out[120]
    DIRECTION OUTPUT ;
    USE SIGNAL ;
    PORT
      LAYER met2 ;
        RECT 2679.590 0.000 2679.870 4.000 ;
    END
  END la_data_out[120]
  PIN la_data_out[121]
    DIRECTION OUTPUT ;
    USE SIGNAL ;
    PORT
      LAYER met2 ;
        RECT 2696.150 0.000 2696.430 4.000 ;
    END
  END la_data_out[121]
  PIN la_data_out[122]
    DIRECTION OUTPUT ;
    USE SIGNAL ;
    PORT
      LAYER met2 ;
        RECT 2712.710 0.000 2712.990 4.000 ;
    END
  END la_data_out[122]
  PIN la_data_out[123]
    DIRECTION OUTPUT ;
    USE SIGNAL ;
    PORT
      LAYER met2 ;
        RECT 2729.270 0.000 2729.550 4.000 ;
    END
  END la_data_out[123]
  PIN la_data_out[124]
    DIRECTION OUTPUT ;
    USE SIGNAL ;
    PORT
      LAYER met2 ;
        RECT 2745.830 0.000 2746.110 4.000 ;
    END
  END la_data_out[124]
  PIN la_data_out[125]
    DIRECTION OUTPUT ;
    USE SIGNAL ;
    PORT
      LAYER met2 ;
        RECT 2762.390 0.000 2762.670 4.000 ;
    END
  END la_data_out[125]
  PIN la_data_out[126]
    DIRECTION OUTPUT ;
    USE SIGNAL ;
    PORT
      LAYER met2 ;
        RECT 2778.950 0.000 2779.230 4.000 ;
    END
  END la_data_out[126]
  PIN la_data_out[127]
    DIRECTION OUTPUT ;
    USE SIGNAL ;
    PORT
      LAYER met2 ;
        RECT 2795.510 0.000 2795.790 4.000 ;
    END
  END la_data_out[127]
  PIN la_data_out[12]
    DIRECTION OUTPUT ;
    USE SIGNAL ;
    ANTENNADIFFAREA 2.673000 ;
    PORT
      LAYER met2 ;
        RECT 891.110 0.000 891.390 4.000 ;
    END
  END la_data_out[12]
  PIN la_data_out[13]
    DIRECTION OUTPUT ;
    USE SIGNAL ;
    ANTENNADIFFAREA 2.673000 ;
    PORT
      LAYER met2 ;
        RECT 907.670 0.000 907.950 4.000 ;
    END
  END la_data_out[13]
  PIN la_data_out[14]
    DIRECTION OUTPUT ;
    USE SIGNAL ;
    ANTENNADIFFAREA 2.673000 ;
    PORT
      LAYER met2 ;
        RECT 924.230 0.000 924.510 4.000 ;
    END
  END la_data_out[14]
  PIN la_data_out[15]
    DIRECTION OUTPUT ;
    USE SIGNAL ;
    ANTENNADIFFAREA 2.673000 ;
    PORT
      LAYER met2 ;
        RECT 940.790 0.000 941.070 4.000 ;
    END
  END la_data_out[15]
  PIN la_data_out[16]
    DIRECTION OUTPUT ;
    USE SIGNAL ;
    ANTENNADIFFAREA 2.673000 ;
    PORT
      LAYER met2 ;
        RECT 957.350 0.000 957.630 4.000 ;
    END
  END la_data_out[16]
  PIN la_data_out[17]
    DIRECTION OUTPUT ;
    USE SIGNAL ;
    ANTENNADIFFAREA 2.673000 ;
    PORT
      LAYER met2 ;
        RECT 973.910 0.000 974.190 4.000 ;
    END
  END la_data_out[17]
  PIN la_data_out[18]
    DIRECTION OUTPUT ;
    USE SIGNAL ;
    ANTENNADIFFAREA 2.673000 ;
    PORT
      LAYER met2 ;
        RECT 990.470 0.000 990.750 4.000 ;
    END
  END la_data_out[18]
  PIN la_data_out[19]
    DIRECTION OUTPUT ;
    USE SIGNAL ;
    ANTENNADIFFAREA 2.673000 ;
    PORT
      LAYER met2 ;
        RECT 1007.030 0.000 1007.310 4.000 ;
    END
  END la_data_out[19]
  PIN la_data_out[1]
    DIRECTION OUTPUT ;
    USE SIGNAL ;
    ANTENNADIFFAREA 2.673000 ;
    PORT
      LAYER met2 ;
        RECT 708.950 0.000 709.230 4.000 ;
    END
  END la_data_out[1]
  PIN la_data_out[20]
    DIRECTION OUTPUT ;
    USE SIGNAL ;
    ANTENNADIFFAREA 2.673000 ;
    PORT
      LAYER met2 ;
        RECT 1023.590 0.000 1023.870 4.000 ;
    END
  END la_data_out[20]
  PIN la_data_out[21]
    DIRECTION OUTPUT ;
    USE SIGNAL ;
    ANTENNADIFFAREA 2.673000 ;
    PORT
      LAYER met2 ;
        RECT 1040.150 0.000 1040.430 4.000 ;
    END
  END la_data_out[21]
  PIN la_data_out[22]
    DIRECTION OUTPUT ;
    USE SIGNAL ;
    ANTENNADIFFAREA 2.673000 ;
    PORT
      LAYER met2 ;
        RECT 1056.710 0.000 1056.990 4.000 ;
    END
  END la_data_out[22]
  PIN la_data_out[23]
    DIRECTION OUTPUT ;
    USE SIGNAL ;
    ANTENNADIFFAREA 2.673000 ;
    PORT
      LAYER met2 ;
        RECT 1073.270 0.000 1073.550 4.000 ;
    END
  END la_data_out[23]
  PIN la_data_out[24]
    DIRECTION OUTPUT ;
    USE SIGNAL ;
    PORT
      LAYER met2 ;
        RECT 1089.830 0.000 1090.110 4.000 ;
    END
  END la_data_out[24]
  PIN la_data_out[25]
    DIRECTION OUTPUT ;
    USE SIGNAL ;
    PORT
      LAYER met2 ;
        RECT 1106.390 0.000 1106.670 4.000 ;
    END
  END la_data_out[25]
  PIN la_data_out[26]
    DIRECTION OUTPUT ;
    USE SIGNAL ;
    PORT
      LAYER met2 ;
        RECT 1122.950 0.000 1123.230 4.000 ;
    END
  END la_data_out[26]
  PIN la_data_out[27]
    DIRECTION OUTPUT ;
    USE SIGNAL ;
    PORT
      LAYER met2 ;
        RECT 1139.510 0.000 1139.790 4.000 ;
    END
  END la_data_out[27]
  PIN la_data_out[28]
    DIRECTION OUTPUT ;
    USE SIGNAL ;
    PORT
      LAYER met2 ;
        RECT 1156.070 0.000 1156.350 4.000 ;
    END
  END la_data_out[28]
  PIN la_data_out[29]
    DIRECTION OUTPUT ;
    USE SIGNAL ;
    PORT
      LAYER met2 ;
        RECT 1172.630 0.000 1172.910 4.000 ;
    END
  END la_data_out[29]
  PIN la_data_out[2]
    DIRECTION OUTPUT ;
    USE SIGNAL ;
    ANTENNADIFFAREA 2.673000 ;
    PORT
      LAYER met2 ;
        RECT 725.510 0.000 725.790 4.000 ;
    END
  END la_data_out[2]
  PIN la_data_out[30]
    DIRECTION OUTPUT ;
    USE SIGNAL ;
    PORT
      LAYER met2 ;
        RECT 1189.190 0.000 1189.470 4.000 ;
    END
  END la_data_out[30]
  PIN la_data_out[31]
    DIRECTION OUTPUT ;
    USE SIGNAL ;
    PORT
      LAYER met2 ;
        RECT 1205.750 0.000 1206.030 4.000 ;
    END
  END la_data_out[31]
  PIN la_data_out[32]
    DIRECTION OUTPUT ;
    USE SIGNAL ;
    PORT
      LAYER met2 ;
        RECT 1222.310 0.000 1222.590 4.000 ;
    END
  END la_data_out[32]
  PIN la_data_out[33]
    DIRECTION OUTPUT ;
    USE SIGNAL ;
    PORT
      LAYER met2 ;
        RECT 1238.870 0.000 1239.150 4.000 ;
    END
  END la_data_out[33]
  PIN la_data_out[34]
    DIRECTION OUTPUT ;
    USE SIGNAL ;
    PORT
      LAYER met2 ;
        RECT 1255.430 0.000 1255.710 4.000 ;
    END
  END la_data_out[34]
  PIN la_data_out[35]
    DIRECTION OUTPUT ;
    USE SIGNAL ;
    PORT
      LAYER met2 ;
        RECT 1271.990 0.000 1272.270 4.000 ;
    END
  END la_data_out[35]
  PIN la_data_out[36]
    DIRECTION OUTPUT ;
    USE SIGNAL ;
    PORT
      LAYER met2 ;
        RECT 1288.550 0.000 1288.830 4.000 ;
    END
  END la_data_out[36]
  PIN la_data_out[37]
    DIRECTION OUTPUT ;
    USE SIGNAL ;
    PORT
      LAYER met2 ;
        RECT 1305.110 0.000 1305.390 4.000 ;
    END
  END la_data_out[37]
  PIN la_data_out[38]
    DIRECTION OUTPUT ;
    USE SIGNAL ;
    PORT
      LAYER met2 ;
        RECT 1321.670 0.000 1321.950 4.000 ;
    END
  END la_data_out[38]
  PIN la_data_out[39]
    DIRECTION OUTPUT ;
    USE SIGNAL ;
    PORT
      LAYER met2 ;
        RECT 1338.230 0.000 1338.510 4.000 ;
    END
  END la_data_out[39]
  PIN la_data_out[3]
    DIRECTION OUTPUT ;
    USE SIGNAL ;
    ANTENNADIFFAREA 2.673000 ;
    PORT
      LAYER met2 ;
        RECT 742.070 0.000 742.350 4.000 ;
    END
  END la_data_out[3]
  PIN la_data_out[40]
    DIRECTION OUTPUT ;
    USE SIGNAL ;
    PORT
      LAYER met2 ;
        RECT 1354.790 0.000 1355.070 4.000 ;
    END
  END la_data_out[40]
  PIN la_data_out[41]
    DIRECTION OUTPUT ;
    USE SIGNAL ;
    PORT
      LAYER met2 ;
        RECT 1371.350 0.000 1371.630 4.000 ;
    END
  END la_data_out[41]
  PIN la_data_out[42]
    DIRECTION OUTPUT ;
    USE SIGNAL ;
    PORT
      LAYER met2 ;
        RECT 1387.910 0.000 1388.190 4.000 ;
    END
  END la_data_out[42]
  PIN la_data_out[43]
    DIRECTION OUTPUT ;
    USE SIGNAL ;
    PORT
      LAYER met2 ;
        RECT 1404.470 0.000 1404.750 4.000 ;
    END
  END la_data_out[43]
  PIN la_data_out[44]
    DIRECTION OUTPUT ;
    USE SIGNAL ;
    PORT
      LAYER met2 ;
        RECT 1421.030 0.000 1421.310 4.000 ;
    END
  END la_data_out[44]
  PIN la_data_out[45]
    DIRECTION OUTPUT ;
    USE SIGNAL ;
    PORT
      LAYER met2 ;
        RECT 1437.590 0.000 1437.870 4.000 ;
    END
  END la_data_out[45]
  PIN la_data_out[46]
    DIRECTION OUTPUT ;
    USE SIGNAL ;
    PORT
      LAYER met2 ;
        RECT 1454.150 0.000 1454.430 4.000 ;
    END
  END la_data_out[46]
  PIN la_data_out[47]
    DIRECTION OUTPUT ;
    USE SIGNAL ;
    PORT
      LAYER met2 ;
        RECT 1470.710 0.000 1470.990 4.000 ;
    END
  END la_data_out[47]
  PIN la_data_out[48]
    DIRECTION OUTPUT ;
    USE SIGNAL ;
    PORT
      LAYER met2 ;
        RECT 1487.270 0.000 1487.550 4.000 ;
    END
  END la_data_out[48]
  PIN la_data_out[49]
    DIRECTION OUTPUT ;
    USE SIGNAL ;
    PORT
      LAYER met2 ;
        RECT 1503.830 0.000 1504.110 4.000 ;
    END
  END la_data_out[49]
  PIN la_data_out[4]
    DIRECTION OUTPUT ;
    USE SIGNAL ;
    ANTENNADIFFAREA 2.673000 ;
    PORT
      LAYER met2 ;
        RECT 758.630 0.000 758.910 4.000 ;
    END
  END la_data_out[4]
  PIN la_data_out[50]
    DIRECTION OUTPUT ;
    USE SIGNAL ;
    PORT
      LAYER met2 ;
        RECT 1520.390 0.000 1520.670 4.000 ;
    END
  END la_data_out[50]
  PIN la_data_out[51]
    DIRECTION OUTPUT ;
    USE SIGNAL ;
    PORT
      LAYER met2 ;
        RECT 1536.950 0.000 1537.230 4.000 ;
    END
  END la_data_out[51]
  PIN la_data_out[52]
    DIRECTION OUTPUT ;
    USE SIGNAL ;
    PORT
      LAYER met2 ;
        RECT 1553.510 0.000 1553.790 4.000 ;
    END
  END la_data_out[52]
  PIN la_data_out[53]
    DIRECTION OUTPUT ;
    USE SIGNAL ;
    PORT
      LAYER met2 ;
        RECT 1570.070 0.000 1570.350 4.000 ;
    END
  END la_data_out[53]
  PIN la_data_out[54]
    DIRECTION OUTPUT ;
    USE SIGNAL ;
    PORT
      LAYER met2 ;
        RECT 1586.630 0.000 1586.910 4.000 ;
    END
  END la_data_out[54]
  PIN la_data_out[55]
    DIRECTION OUTPUT ;
    USE SIGNAL ;
    PORT
      LAYER met2 ;
        RECT 1603.190 0.000 1603.470 4.000 ;
    END
  END la_data_out[55]
  PIN la_data_out[56]
    DIRECTION OUTPUT ;
    USE SIGNAL ;
    PORT
      LAYER met2 ;
        RECT 1619.750 0.000 1620.030 4.000 ;
    END
  END la_data_out[56]
  PIN la_data_out[57]
    DIRECTION OUTPUT ;
    USE SIGNAL ;
    PORT
      LAYER met2 ;
        RECT 1636.310 0.000 1636.590 4.000 ;
    END
  END la_data_out[57]
  PIN la_data_out[58]
    DIRECTION OUTPUT ;
    USE SIGNAL ;
    PORT
      LAYER met2 ;
        RECT 1652.870 0.000 1653.150 4.000 ;
    END
  END la_data_out[58]
  PIN la_data_out[59]
    DIRECTION OUTPUT ;
    USE SIGNAL ;
    PORT
      LAYER met2 ;
        RECT 1669.430 0.000 1669.710 4.000 ;
    END
  END la_data_out[59]
  PIN la_data_out[5]
    DIRECTION OUTPUT ;
    USE SIGNAL ;
    ANTENNADIFFAREA 2.673000 ;
    PORT
      LAYER met2 ;
        RECT 775.190 0.000 775.470 4.000 ;
    END
  END la_data_out[5]
  PIN la_data_out[60]
    DIRECTION OUTPUT ;
    USE SIGNAL ;
    PORT
      LAYER met2 ;
        RECT 1685.990 0.000 1686.270 4.000 ;
    END
  END la_data_out[60]
  PIN la_data_out[61]
    DIRECTION OUTPUT ;
    USE SIGNAL ;
    PORT
      LAYER met2 ;
        RECT 1702.550 0.000 1702.830 4.000 ;
    END
  END la_data_out[61]
  PIN la_data_out[62]
    DIRECTION OUTPUT ;
    USE SIGNAL ;
    PORT
      LAYER met2 ;
        RECT 1719.110 0.000 1719.390 4.000 ;
    END
  END la_data_out[62]
  PIN la_data_out[63]
    DIRECTION OUTPUT ;
    USE SIGNAL ;
    PORT
      LAYER met2 ;
        RECT 1735.670 0.000 1735.950 4.000 ;
    END
  END la_data_out[63]
  PIN la_data_out[64]
    DIRECTION OUTPUT ;
    USE SIGNAL ;
    PORT
      LAYER met2 ;
        RECT 1752.230 0.000 1752.510 4.000 ;
    END
  END la_data_out[64]
  PIN la_data_out[65]
    DIRECTION OUTPUT ;
    USE SIGNAL ;
    PORT
      LAYER met2 ;
        RECT 1768.790 0.000 1769.070 4.000 ;
    END
  END la_data_out[65]
  PIN la_data_out[66]
    DIRECTION OUTPUT ;
    USE SIGNAL ;
    PORT
      LAYER met2 ;
        RECT 1785.350 0.000 1785.630 4.000 ;
    END
  END la_data_out[66]
  PIN la_data_out[67]
    DIRECTION OUTPUT ;
    USE SIGNAL ;
    PORT
      LAYER met2 ;
        RECT 1801.910 0.000 1802.190 4.000 ;
    END
  END la_data_out[67]
  PIN la_data_out[68]
    DIRECTION OUTPUT ;
    USE SIGNAL ;
    PORT
      LAYER met2 ;
        RECT 1818.470 0.000 1818.750 4.000 ;
    END
  END la_data_out[68]
  PIN la_data_out[69]
    DIRECTION OUTPUT ;
    USE SIGNAL ;
    PORT
      LAYER met2 ;
        RECT 1835.030 0.000 1835.310 4.000 ;
    END
  END la_data_out[69]
  PIN la_data_out[6]
    DIRECTION OUTPUT ;
    USE SIGNAL ;
    ANTENNADIFFAREA 2.673000 ;
    PORT
      LAYER met2 ;
        RECT 791.750 0.000 792.030 4.000 ;
    END
  END la_data_out[6]
  PIN la_data_out[70]
    DIRECTION OUTPUT ;
    USE SIGNAL ;
    PORT
      LAYER met2 ;
        RECT 1851.590 0.000 1851.870 4.000 ;
    END
  END la_data_out[70]
  PIN la_data_out[71]
    DIRECTION OUTPUT ;
    USE SIGNAL ;
    PORT
      LAYER met2 ;
        RECT 1868.150 0.000 1868.430 4.000 ;
    END
  END la_data_out[71]
  PIN la_data_out[72]
    DIRECTION OUTPUT ;
    USE SIGNAL ;
    PORT
      LAYER met2 ;
        RECT 1884.710 0.000 1884.990 4.000 ;
    END
  END la_data_out[72]
  PIN la_data_out[73]
    DIRECTION OUTPUT ;
    USE SIGNAL ;
    PORT
      LAYER met2 ;
        RECT 1901.270 0.000 1901.550 4.000 ;
    END
  END la_data_out[73]
  PIN la_data_out[74]
    DIRECTION OUTPUT ;
    USE SIGNAL ;
    PORT
      LAYER met2 ;
        RECT 1917.830 0.000 1918.110 4.000 ;
    END
  END la_data_out[74]
  PIN la_data_out[75]
    DIRECTION OUTPUT ;
    USE SIGNAL ;
    PORT
      LAYER met2 ;
        RECT 1934.390 0.000 1934.670 4.000 ;
    END
  END la_data_out[75]
  PIN la_data_out[76]
    DIRECTION OUTPUT ;
    USE SIGNAL ;
    PORT
      LAYER met2 ;
        RECT 1950.950 0.000 1951.230 4.000 ;
    END
  END la_data_out[76]
  PIN la_data_out[77]
    DIRECTION OUTPUT ;
    USE SIGNAL ;
    PORT
      LAYER met2 ;
        RECT 1967.510 0.000 1967.790 4.000 ;
    END
  END la_data_out[77]
  PIN la_data_out[78]
    DIRECTION OUTPUT ;
    USE SIGNAL ;
    PORT
      LAYER met2 ;
        RECT 1984.070 0.000 1984.350 4.000 ;
    END
  END la_data_out[78]
  PIN la_data_out[79]
    DIRECTION OUTPUT ;
    USE SIGNAL ;
    PORT
      LAYER met2 ;
        RECT 2000.630 0.000 2000.910 4.000 ;
    END
  END la_data_out[79]
  PIN la_data_out[7]
    DIRECTION OUTPUT ;
    USE SIGNAL ;
    ANTENNADIFFAREA 2.673000 ;
    PORT
      LAYER met2 ;
        RECT 808.310 0.000 808.590 4.000 ;
    END
  END la_data_out[7]
  PIN la_data_out[80]
    DIRECTION OUTPUT ;
    USE SIGNAL ;
    PORT
      LAYER met2 ;
        RECT 2017.190 0.000 2017.470 4.000 ;
    END
  END la_data_out[80]
  PIN la_data_out[81]
    DIRECTION OUTPUT ;
    USE SIGNAL ;
    PORT
      LAYER met2 ;
        RECT 2033.750 0.000 2034.030 4.000 ;
    END
  END la_data_out[81]
  PIN la_data_out[82]
    DIRECTION OUTPUT ;
    USE SIGNAL ;
    PORT
      LAYER met2 ;
        RECT 2050.310 0.000 2050.590 4.000 ;
    END
  END la_data_out[82]
  PIN la_data_out[83]
    DIRECTION OUTPUT ;
    USE SIGNAL ;
    PORT
      LAYER met2 ;
        RECT 2066.870 0.000 2067.150 4.000 ;
    END
  END la_data_out[83]
  PIN la_data_out[84]
    DIRECTION OUTPUT ;
    USE SIGNAL ;
    PORT
      LAYER met2 ;
        RECT 2083.430 0.000 2083.710 4.000 ;
    END
  END la_data_out[84]
  PIN la_data_out[85]
    DIRECTION OUTPUT ;
    USE SIGNAL ;
    PORT
      LAYER met2 ;
        RECT 2099.990 0.000 2100.270 4.000 ;
    END
  END la_data_out[85]
  PIN la_data_out[86]
    DIRECTION OUTPUT ;
    USE SIGNAL ;
    PORT
      LAYER met2 ;
        RECT 2116.550 0.000 2116.830 4.000 ;
    END
  END la_data_out[86]
  PIN la_data_out[87]
    DIRECTION OUTPUT ;
    USE SIGNAL ;
    PORT
      LAYER met2 ;
        RECT 2133.110 0.000 2133.390 4.000 ;
    END
  END la_data_out[87]
  PIN la_data_out[88]
    DIRECTION OUTPUT ;
    USE SIGNAL ;
    PORT
      LAYER met2 ;
        RECT 2149.670 0.000 2149.950 4.000 ;
    END
  END la_data_out[88]
  PIN la_data_out[89]
    DIRECTION OUTPUT ;
    USE SIGNAL ;
    PORT
      LAYER met2 ;
        RECT 2166.230 0.000 2166.510 4.000 ;
    END
  END la_data_out[89]
  PIN la_data_out[8]
    DIRECTION OUTPUT ;
    USE SIGNAL ;
    ANTENNADIFFAREA 2.673000 ;
    PORT
      LAYER met2 ;
        RECT 824.870 0.000 825.150 4.000 ;
    END
  END la_data_out[8]
  PIN la_data_out[90]
    DIRECTION OUTPUT ;
    USE SIGNAL ;
    PORT
      LAYER met2 ;
        RECT 2182.790 0.000 2183.070 4.000 ;
    END
  END la_data_out[90]
  PIN la_data_out[91]
    DIRECTION OUTPUT ;
    USE SIGNAL ;
    PORT
      LAYER met2 ;
        RECT 2199.350 0.000 2199.630 4.000 ;
    END
  END la_data_out[91]
  PIN la_data_out[92]
    DIRECTION OUTPUT ;
    USE SIGNAL ;
    PORT
      LAYER met2 ;
        RECT 2215.910 0.000 2216.190 4.000 ;
    END
  END la_data_out[92]
  PIN la_data_out[93]
    DIRECTION OUTPUT ;
    USE SIGNAL ;
    PORT
      LAYER met2 ;
        RECT 2232.470 0.000 2232.750 4.000 ;
    END
  END la_data_out[93]
  PIN la_data_out[94]
    DIRECTION OUTPUT ;
    USE SIGNAL ;
    PORT
      LAYER met2 ;
        RECT 2249.030 0.000 2249.310 4.000 ;
    END
  END la_data_out[94]
  PIN la_data_out[95]
    DIRECTION OUTPUT ;
    USE SIGNAL ;
    PORT
      LAYER met2 ;
        RECT 2265.590 0.000 2265.870 4.000 ;
    END
  END la_data_out[95]
  PIN la_data_out[96]
    DIRECTION OUTPUT ;
    USE SIGNAL ;
    PORT
      LAYER met2 ;
        RECT 2282.150 0.000 2282.430 4.000 ;
    END
  END la_data_out[96]
  PIN la_data_out[97]
    DIRECTION OUTPUT ;
    USE SIGNAL ;
    PORT
      LAYER met2 ;
        RECT 2298.710 0.000 2298.990 4.000 ;
    END
  END la_data_out[97]
  PIN la_data_out[98]
    DIRECTION OUTPUT ;
    USE SIGNAL ;
    PORT
      LAYER met2 ;
        RECT 2315.270 0.000 2315.550 4.000 ;
    END
  END la_data_out[98]
  PIN la_data_out[99]
    DIRECTION OUTPUT ;
    USE SIGNAL ;
    PORT
      LAYER met2 ;
        RECT 2331.830 0.000 2332.110 4.000 ;
    END
  END la_data_out[99]
  PIN la_data_out[9]
    DIRECTION OUTPUT ;
    USE SIGNAL ;
    ANTENNADIFFAREA 2.673000 ;
    PORT
      LAYER met2 ;
        RECT 841.430 0.000 841.710 4.000 ;
    END
  END la_data_out[9]
  PIN la_oenb[0]
    DIRECTION INPUT ;
    USE SIGNAL ;
    PORT
      LAYER met2 ;
        RECT 697.910 0.000 698.190 4.000 ;
    END
  END la_oenb[0]
  PIN la_oenb[100]
    DIRECTION INPUT ;
    USE SIGNAL ;
    PORT
      LAYER met2 ;
        RECT 2353.910 0.000 2354.190 4.000 ;
    END
  END la_oenb[100]
  PIN la_oenb[101]
    DIRECTION INPUT ;
    USE SIGNAL ;
    PORT
      LAYER met2 ;
        RECT 2370.470 0.000 2370.750 4.000 ;
    END
  END la_oenb[101]
  PIN la_oenb[102]
    DIRECTION INPUT ;
    USE SIGNAL ;
    PORT
      LAYER met2 ;
        RECT 2387.030 0.000 2387.310 4.000 ;
    END
  END la_oenb[102]
  PIN la_oenb[103]
    DIRECTION INPUT ;
    USE SIGNAL ;
    PORT
      LAYER met2 ;
        RECT 2403.590 0.000 2403.870 4.000 ;
    END
  END la_oenb[103]
  PIN la_oenb[104]
    DIRECTION INPUT ;
    USE SIGNAL ;
    PORT
      LAYER met2 ;
        RECT 2420.150 0.000 2420.430 4.000 ;
    END
  END la_oenb[104]
  PIN la_oenb[105]
    DIRECTION INPUT ;
    USE SIGNAL ;
    PORT
      LAYER met2 ;
        RECT 2436.710 0.000 2436.990 4.000 ;
    END
  END la_oenb[105]
  PIN la_oenb[106]
    DIRECTION INPUT ;
    USE SIGNAL ;
    PORT
      LAYER met2 ;
        RECT 2453.270 0.000 2453.550 4.000 ;
    END
  END la_oenb[106]
  PIN la_oenb[107]
    DIRECTION INPUT ;
    USE SIGNAL ;
    PORT
      LAYER met2 ;
        RECT 2469.830 0.000 2470.110 4.000 ;
    END
  END la_oenb[107]
  PIN la_oenb[108]
    DIRECTION INPUT ;
    USE SIGNAL ;
    PORT
      LAYER met2 ;
        RECT 2486.390 0.000 2486.670 4.000 ;
    END
  END la_oenb[108]
  PIN la_oenb[109]
    DIRECTION INPUT ;
    USE SIGNAL ;
    PORT
      LAYER met2 ;
        RECT 2502.950 0.000 2503.230 4.000 ;
    END
  END la_oenb[109]
  PIN la_oenb[10]
    DIRECTION INPUT ;
    USE SIGNAL ;
    PORT
      LAYER met2 ;
        RECT 863.510 0.000 863.790 4.000 ;
    END
  END la_oenb[10]
  PIN la_oenb[110]
    DIRECTION INPUT ;
    USE SIGNAL ;
    PORT
      LAYER met2 ;
        RECT 2519.510 0.000 2519.790 4.000 ;
    END
  END la_oenb[110]
  PIN la_oenb[111]
    DIRECTION INPUT ;
    USE SIGNAL ;
    PORT
      LAYER met2 ;
        RECT 2536.070 0.000 2536.350 4.000 ;
    END
  END la_oenb[111]
  PIN la_oenb[112]
    DIRECTION INPUT ;
    USE SIGNAL ;
    PORT
      LAYER met2 ;
        RECT 2552.630 0.000 2552.910 4.000 ;
    END
  END la_oenb[112]
  PIN la_oenb[113]
    DIRECTION INPUT ;
    USE SIGNAL ;
    PORT
      LAYER met2 ;
        RECT 2569.190 0.000 2569.470 4.000 ;
    END
  END la_oenb[113]
  PIN la_oenb[114]
    DIRECTION INPUT ;
    USE SIGNAL ;
    PORT
      LAYER met2 ;
        RECT 2585.750 0.000 2586.030 4.000 ;
    END
  END la_oenb[114]
  PIN la_oenb[115]
    DIRECTION INPUT ;
    USE SIGNAL ;
    PORT
      LAYER met2 ;
        RECT 2602.310 0.000 2602.590 4.000 ;
    END
  END la_oenb[115]
  PIN la_oenb[116]
    DIRECTION INPUT ;
    USE SIGNAL ;
    PORT
      LAYER met2 ;
        RECT 2618.870 0.000 2619.150 4.000 ;
    END
  END la_oenb[116]
  PIN la_oenb[117]
    DIRECTION INPUT ;
    USE SIGNAL ;
    PORT
      LAYER met2 ;
        RECT 2635.430 0.000 2635.710 4.000 ;
    END
  END la_oenb[117]
  PIN la_oenb[118]
    DIRECTION INPUT ;
    USE SIGNAL ;
    PORT
      LAYER met2 ;
        RECT 2651.990 0.000 2652.270 4.000 ;
    END
  END la_oenb[118]
  PIN la_oenb[119]
    DIRECTION INPUT ;
    USE SIGNAL ;
    PORT
      LAYER met2 ;
        RECT 2668.550 0.000 2668.830 4.000 ;
    END
  END la_oenb[119]
  PIN la_oenb[11]
    DIRECTION INPUT ;
    USE SIGNAL ;
    PORT
      LAYER met2 ;
        RECT 880.070 0.000 880.350 4.000 ;
    END
  END la_oenb[11]
  PIN la_oenb[120]
    DIRECTION INPUT ;
    USE SIGNAL ;
    PORT
      LAYER met2 ;
        RECT 2685.110 0.000 2685.390 4.000 ;
    END
  END la_oenb[120]
  PIN la_oenb[121]
    DIRECTION INPUT ;
    USE SIGNAL ;
    PORT
      LAYER met2 ;
        RECT 2701.670 0.000 2701.950 4.000 ;
    END
  END la_oenb[121]
  PIN la_oenb[122]
    DIRECTION INPUT ;
    USE SIGNAL ;
    PORT
      LAYER met2 ;
        RECT 2718.230 0.000 2718.510 4.000 ;
    END
  END la_oenb[122]
  PIN la_oenb[123]
    DIRECTION INPUT ;
    USE SIGNAL ;
    PORT
      LAYER met2 ;
        RECT 2734.790 0.000 2735.070 4.000 ;
    END
  END la_oenb[123]
  PIN la_oenb[124]
    DIRECTION INPUT ;
    USE SIGNAL ;
    PORT
      LAYER met2 ;
        RECT 2751.350 0.000 2751.630 4.000 ;
    END
  END la_oenb[124]
  PIN la_oenb[125]
    DIRECTION INPUT ;
    USE SIGNAL ;
    PORT
      LAYER met2 ;
        RECT 2767.910 0.000 2768.190 4.000 ;
    END
  END la_oenb[125]
  PIN la_oenb[126]
    DIRECTION INPUT ;
    USE SIGNAL ;
    PORT
      LAYER met2 ;
        RECT 2784.470 0.000 2784.750 4.000 ;
    END
  END la_oenb[126]
  PIN la_oenb[127]
    DIRECTION INPUT ;
    USE SIGNAL ;
    PORT
      LAYER met2 ;
        RECT 2801.030 0.000 2801.310 4.000 ;
    END
  END la_oenb[127]
  PIN la_oenb[12]
    DIRECTION INPUT ;
    USE SIGNAL ;
    PORT
      LAYER met2 ;
        RECT 896.630 0.000 896.910 4.000 ;
    END
  END la_oenb[12]
  PIN la_oenb[13]
    DIRECTION INPUT ;
    USE SIGNAL ;
    PORT
      LAYER met2 ;
        RECT 913.190 0.000 913.470 4.000 ;
    END
  END la_oenb[13]
  PIN la_oenb[14]
    DIRECTION INPUT ;
    USE SIGNAL ;
    PORT
      LAYER met2 ;
        RECT 929.750 0.000 930.030 4.000 ;
    END
  END la_oenb[14]
  PIN la_oenb[15]
    DIRECTION INPUT ;
    USE SIGNAL ;
    PORT
      LAYER met2 ;
        RECT 946.310 0.000 946.590 4.000 ;
    END
  END la_oenb[15]
  PIN la_oenb[16]
    DIRECTION INPUT ;
    USE SIGNAL ;
    PORT
      LAYER met2 ;
        RECT 962.870 0.000 963.150 4.000 ;
    END
  END la_oenb[16]
  PIN la_oenb[17]
    DIRECTION INPUT ;
    USE SIGNAL ;
    PORT
      LAYER met2 ;
        RECT 979.430 0.000 979.710 4.000 ;
    END
  END la_oenb[17]
  PIN la_oenb[18]
    DIRECTION INPUT ;
    USE SIGNAL ;
    PORT
      LAYER met2 ;
        RECT 995.990 0.000 996.270 4.000 ;
    END
  END la_oenb[18]
  PIN la_oenb[19]
    DIRECTION INPUT ;
    USE SIGNAL ;
    PORT
      LAYER met2 ;
        RECT 1012.550 0.000 1012.830 4.000 ;
    END
  END la_oenb[19]
  PIN la_oenb[1]
    DIRECTION INPUT ;
    USE SIGNAL ;
    PORT
      LAYER met2 ;
        RECT 714.470 0.000 714.750 4.000 ;
    END
  END la_oenb[1]
  PIN la_oenb[20]
    DIRECTION INPUT ;
    USE SIGNAL ;
    PORT
      LAYER met2 ;
        RECT 1029.110 0.000 1029.390 4.000 ;
    END
  END la_oenb[20]
  PIN la_oenb[21]
    DIRECTION INPUT ;
    USE SIGNAL ;
    PORT
      LAYER met2 ;
        RECT 1045.670 0.000 1045.950 4.000 ;
    END
  END la_oenb[21]
  PIN la_oenb[22]
    DIRECTION INPUT ;
    USE SIGNAL ;
    PORT
      LAYER met2 ;
        RECT 1062.230 0.000 1062.510 4.000 ;
    END
  END la_oenb[22]
  PIN la_oenb[23]
    DIRECTION INPUT ;
    USE SIGNAL ;
    PORT
      LAYER met2 ;
        RECT 1078.790 0.000 1079.070 4.000 ;
    END
  END la_oenb[23]
  PIN la_oenb[24]
    DIRECTION INPUT ;
    USE SIGNAL ;
    PORT
      LAYER met2 ;
        RECT 1095.350 0.000 1095.630 4.000 ;
    END
  END la_oenb[24]
  PIN la_oenb[25]
    DIRECTION INPUT ;
    USE SIGNAL ;
    PORT
      LAYER met2 ;
        RECT 1111.910 0.000 1112.190 4.000 ;
    END
  END la_oenb[25]
  PIN la_oenb[26]
    DIRECTION INPUT ;
    USE SIGNAL ;
    PORT
      LAYER met2 ;
        RECT 1128.470 0.000 1128.750 4.000 ;
    END
  END la_oenb[26]
  PIN la_oenb[27]
    DIRECTION INPUT ;
    USE SIGNAL ;
    PORT
      LAYER met2 ;
        RECT 1145.030 0.000 1145.310 4.000 ;
    END
  END la_oenb[27]
  PIN la_oenb[28]
    DIRECTION INPUT ;
    USE SIGNAL ;
    PORT
      LAYER met2 ;
        RECT 1161.590 0.000 1161.870 4.000 ;
    END
  END la_oenb[28]
  PIN la_oenb[29]
    DIRECTION INPUT ;
    USE SIGNAL ;
    PORT
      LAYER met2 ;
        RECT 1178.150 0.000 1178.430 4.000 ;
    END
  END la_oenb[29]
  PIN la_oenb[2]
    DIRECTION INPUT ;
    USE SIGNAL ;
    PORT
      LAYER met2 ;
        RECT 731.030 0.000 731.310 4.000 ;
    END
  END la_oenb[2]
  PIN la_oenb[30]
    DIRECTION INPUT ;
    USE SIGNAL ;
    PORT
      LAYER met2 ;
        RECT 1194.710 0.000 1194.990 4.000 ;
    END
  END la_oenb[30]
  PIN la_oenb[31]
    DIRECTION INPUT ;
    USE SIGNAL ;
    PORT
      LAYER met2 ;
        RECT 1211.270 0.000 1211.550 4.000 ;
    END
  END la_oenb[31]
  PIN la_oenb[32]
    DIRECTION INPUT ;
    USE SIGNAL ;
    PORT
      LAYER met2 ;
        RECT 1227.830 0.000 1228.110 4.000 ;
    END
  END la_oenb[32]
  PIN la_oenb[33]
    DIRECTION INPUT ;
    USE SIGNAL ;
    PORT
      LAYER met2 ;
        RECT 1244.390 0.000 1244.670 4.000 ;
    END
  END la_oenb[33]
  PIN la_oenb[34]
    DIRECTION INPUT ;
    USE SIGNAL ;
    PORT
      LAYER met2 ;
        RECT 1260.950 0.000 1261.230 4.000 ;
    END
  END la_oenb[34]
  PIN la_oenb[35]
    DIRECTION INPUT ;
    USE SIGNAL ;
    PORT
      LAYER met2 ;
        RECT 1277.510 0.000 1277.790 4.000 ;
    END
  END la_oenb[35]
  PIN la_oenb[36]
    DIRECTION INPUT ;
    USE SIGNAL ;
    PORT
      LAYER met2 ;
        RECT 1294.070 0.000 1294.350 4.000 ;
    END
  END la_oenb[36]
  PIN la_oenb[37]
    DIRECTION INPUT ;
    USE SIGNAL ;
    PORT
      LAYER met2 ;
        RECT 1310.630 0.000 1310.910 4.000 ;
    END
  END la_oenb[37]
  PIN la_oenb[38]
    DIRECTION INPUT ;
    USE SIGNAL ;
    PORT
      LAYER met2 ;
        RECT 1327.190 0.000 1327.470 4.000 ;
    END
  END la_oenb[38]
  PIN la_oenb[39]
    DIRECTION INPUT ;
    USE SIGNAL ;
    PORT
      LAYER met2 ;
        RECT 1343.750 0.000 1344.030 4.000 ;
    END
  END la_oenb[39]
  PIN la_oenb[3]
    DIRECTION INPUT ;
    USE SIGNAL ;
    PORT
      LAYER met2 ;
        RECT 747.590 0.000 747.870 4.000 ;
    END
  END la_oenb[3]
  PIN la_oenb[40]
    DIRECTION INPUT ;
    USE SIGNAL ;
    PORT
      LAYER met2 ;
        RECT 1360.310 0.000 1360.590 4.000 ;
    END
  END la_oenb[40]
  PIN la_oenb[41]
    DIRECTION INPUT ;
    USE SIGNAL ;
    PORT
      LAYER met2 ;
        RECT 1376.870 0.000 1377.150 4.000 ;
    END
  END la_oenb[41]
  PIN la_oenb[42]
    DIRECTION INPUT ;
    USE SIGNAL ;
    PORT
      LAYER met2 ;
        RECT 1393.430 0.000 1393.710 4.000 ;
    END
  END la_oenb[42]
  PIN la_oenb[43]
    DIRECTION INPUT ;
    USE SIGNAL ;
    PORT
      LAYER met2 ;
        RECT 1409.990 0.000 1410.270 4.000 ;
    END
  END la_oenb[43]
  PIN la_oenb[44]
    DIRECTION INPUT ;
    USE SIGNAL ;
    PORT
      LAYER met2 ;
        RECT 1426.550 0.000 1426.830 4.000 ;
    END
  END la_oenb[44]
  PIN la_oenb[45]
    DIRECTION INPUT ;
    USE SIGNAL ;
    PORT
      LAYER met2 ;
        RECT 1443.110 0.000 1443.390 4.000 ;
    END
  END la_oenb[45]
  PIN la_oenb[46]
    DIRECTION INPUT ;
    USE SIGNAL ;
    PORT
      LAYER met2 ;
        RECT 1459.670 0.000 1459.950 4.000 ;
    END
  END la_oenb[46]
  PIN la_oenb[47]
    DIRECTION INPUT ;
    USE SIGNAL ;
    PORT
      LAYER met2 ;
        RECT 1476.230 0.000 1476.510 4.000 ;
    END
  END la_oenb[47]
  PIN la_oenb[48]
    DIRECTION INPUT ;
    USE SIGNAL ;
    PORT
      LAYER met2 ;
        RECT 1492.790 0.000 1493.070 4.000 ;
    END
  END la_oenb[48]
  PIN la_oenb[49]
    DIRECTION INPUT ;
    USE SIGNAL ;
    PORT
      LAYER met2 ;
        RECT 1509.350 0.000 1509.630 4.000 ;
    END
  END la_oenb[49]
  PIN la_oenb[4]
    DIRECTION INPUT ;
    USE SIGNAL ;
    PORT
      LAYER met2 ;
        RECT 764.150 0.000 764.430 4.000 ;
    END
  END la_oenb[4]
  PIN la_oenb[50]
    DIRECTION INPUT ;
    USE SIGNAL ;
    PORT
      LAYER met2 ;
        RECT 1525.910 0.000 1526.190 4.000 ;
    END
  END la_oenb[50]
  PIN la_oenb[51]
    DIRECTION INPUT ;
    USE SIGNAL ;
    PORT
      LAYER met2 ;
        RECT 1542.470 0.000 1542.750 4.000 ;
    END
  END la_oenb[51]
  PIN la_oenb[52]
    DIRECTION INPUT ;
    USE SIGNAL ;
    PORT
      LAYER met2 ;
        RECT 1559.030 0.000 1559.310 4.000 ;
    END
  END la_oenb[52]
  PIN la_oenb[53]
    DIRECTION INPUT ;
    USE SIGNAL ;
    PORT
      LAYER met2 ;
        RECT 1575.590 0.000 1575.870 4.000 ;
    END
  END la_oenb[53]
  PIN la_oenb[54]
    DIRECTION INPUT ;
    USE SIGNAL ;
    PORT
      LAYER met2 ;
        RECT 1592.150 0.000 1592.430 4.000 ;
    END
  END la_oenb[54]
  PIN la_oenb[55]
    DIRECTION INPUT ;
    USE SIGNAL ;
    PORT
      LAYER met2 ;
        RECT 1608.710 0.000 1608.990 4.000 ;
    END
  END la_oenb[55]
  PIN la_oenb[56]
    DIRECTION INPUT ;
    USE SIGNAL ;
    PORT
      LAYER met2 ;
        RECT 1625.270 0.000 1625.550 4.000 ;
    END
  END la_oenb[56]
  PIN la_oenb[57]
    DIRECTION INPUT ;
    USE SIGNAL ;
    PORT
      LAYER met2 ;
        RECT 1641.830 0.000 1642.110 4.000 ;
    END
  END la_oenb[57]
  PIN la_oenb[58]
    DIRECTION INPUT ;
    USE SIGNAL ;
    PORT
      LAYER met2 ;
        RECT 1658.390 0.000 1658.670 4.000 ;
    END
  END la_oenb[58]
  PIN la_oenb[59]
    DIRECTION INPUT ;
    USE SIGNAL ;
    PORT
      LAYER met2 ;
        RECT 1674.950 0.000 1675.230 4.000 ;
    END
  END la_oenb[59]
  PIN la_oenb[5]
    DIRECTION INPUT ;
    USE SIGNAL ;
    PORT
      LAYER met2 ;
        RECT 780.710 0.000 780.990 4.000 ;
    END
  END la_oenb[5]
  PIN la_oenb[60]
    DIRECTION INPUT ;
    USE SIGNAL ;
    PORT
      LAYER met2 ;
        RECT 1691.510 0.000 1691.790 4.000 ;
    END
  END la_oenb[60]
  PIN la_oenb[61]
    DIRECTION INPUT ;
    USE SIGNAL ;
    PORT
      LAYER met2 ;
        RECT 1708.070 0.000 1708.350 4.000 ;
    END
  END la_oenb[61]
  PIN la_oenb[62]
    DIRECTION INPUT ;
    USE SIGNAL ;
    PORT
      LAYER met2 ;
        RECT 1724.630 0.000 1724.910 4.000 ;
    END
  END la_oenb[62]
  PIN la_oenb[63]
    DIRECTION INPUT ;
    USE SIGNAL ;
    PORT
      LAYER met2 ;
        RECT 1741.190 0.000 1741.470 4.000 ;
    END
  END la_oenb[63]
  PIN la_oenb[64]
    DIRECTION INPUT ;
    USE SIGNAL ;
    PORT
      LAYER met2 ;
        RECT 1757.750 0.000 1758.030 4.000 ;
    END
  END la_oenb[64]
  PIN la_oenb[65]
    DIRECTION INPUT ;
    USE SIGNAL ;
    PORT
      LAYER met2 ;
        RECT 1774.310 0.000 1774.590 4.000 ;
    END
  END la_oenb[65]
  PIN la_oenb[66]
    DIRECTION INPUT ;
    USE SIGNAL ;
    PORT
      LAYER met2 ;
        RECT 1790.870 0.000 1791.150 4.000 ;
    END
  END la_oenb[66]
  PIN la_oenb[67]
    DIRECTION INPUT ;
    USE SIGNAL ;
    PORT
      LAYER met2 ;
        RECT 1807.430 0.000 1807.710 4.000 ;
    END
  END la_oenb[67]
  PIN la_oenb[68]
    DIRECTION INPUT ;
    USE SIGNAL ;
    PORT
      LAYER met2 ;
        RECT 1823.990 0.000 1824.270 4.000 ;
    END
  END la_oenb[68]
  PIN la_oenb[69]
    DIRECTION INPUT ;
    USE SIGNAL ;
    PORT
      LAYER met2 ;
        RECT 1840.550 0.000 1840.830 4.000 ;
    END
  END la_oenb[69]
  PIN la_oenb[6]
    DIRECTION INPUT ;
    USE SIGNAL ;
    PORT
      LAYER met2 ;
        RECT 797.270 0.000 797.550 4.000 ;
    END
  END la_oenb[6]
  PIN la_oenb[70]
    DIRECTION INPUT ;
    USE SIGNAL ;
    PORT
      LAYER met2 ;
        RECT 1857.110 0.000 1857.390 4.000 ;
    END
  END la_oenb[70]
  PIN la_oenb[71]
    DIRECTION INPUT ;
    USE SIGNAL ;
    PORT
      LAYER met2 ;
        RECT 1873.670 0.000 1873.950 4.000 ;
    END
  END la_oenb[71]
  PIN la_oenb[72]
    DIRECTION INPUT ;
    USE SIGNAL ;
    PORT
      LAYER met2 ;
        RECT 1890.230 0.000 1890.510 4.000 ;
    END
  END la_oenb[72]
  PIN la_oenb[73]
    DIRECTION INPUT ;
    USE SIGNAL ;
    PORT
      LAYER met2 ;
        RECT 1906.790 0.000 1907.070 4.000 ;
    END
  END la_oenb[73]
  PIN la_oenb[74]
    DIRECTION INPUT ;
    USE SIGNAL ;
    PORT
      LAYER met2 ;
        RECT 1923.350 0.000 1923.630 4.000 ;
    END
  END la_oenb[74]
  PIN la_oenb[75]
    DIRECTION INPUT ;
    USE SIGNAL ;
    PORT
      LAYER met2 ;
        RECT 1939.910 0.000 1940.190 4.000 ;
    END
  END la_oenb[75]
  PIN la_oenb[76]
    DIRECTION INPUT ;
    USE SIGNAL ;
    PORT
      LAYER met2 ;
        RECT 1956.470 0.000 1956.750 4.000 ;
    END
  END la_oenb[76]
  PIN la_oenb[77]
    DIRECTION INPUT ;
    USE SIGNAL ;
    PORT
      LAYER met2 ;
        RECT 1973.030 0.000 1973.310 4.000 ;
    END
  END la_oenb[77]
  PIN la_oenb[78]
    DIRECTION INPUT ;
    USE SIGNAL ;
    PORT
      LAYER met2 ;
        RECT 1989.590 0.000 1989.870 4.000 ;
    END
  END la_oenb[78]
  PIN la_oenb[79]
    DIRECTION INPUT ;
    USE SIGNAL ;
    PORT
      LAYER met2 ;
        RECT 2006.150 0.000 2006.430 4.000 ;
    END
  END la_oenb[79]
  PIN la_oenb[7]
    DIRECTION INPUT ;
    USE SIGNAL ;
    PORT
      LAYER met2 ;
        RECT 813.830 0.000 814.110 4.000 ;
    END
  END la_oenb[7]
  PIN la_oenb[80]
    DIRECTION INPUT ;
    USE SIGNAL ;
    PORT
      LAYER met2 ;
        RECT 2022.710 0.000 2022.990 4.000 ;
    END
  END la_oenb[80]
  PIN la_oenb[81]
    DIRECTION INPUT ;
    USE SIGNAL ;
    PORT
      LAYER met2 ;
        RECT 2039.270 0.000 2039.550 4.000 ;
    END
  END la_oenb[81]
  PIN la_oenb[82]
    DIRECTION INPUT ;
    USE SIGNAL ;
    PORT
      LAYER met2 ;
        RECT 2055.830 0.000 2056.110 4.000 ;
    END
  END la_oenb[82]
  PIN la_oenb[83]
    DIRECTION INPUT ;
    USE SIGNAL ;
    PORT
      LAYER met2 ;
        RECT 2072.390 0.000 2072.670 4.000 ;
    END
  END la_oenb[83]
  PIN la_oenb[84]
    DIRECTION INPUT ;
    USE SIGNAL ;
    PORT
      LAYER met2 ;
        RECT 2088.950 0.000 2089.230 4.000 ;
    END
  END la_oenb[84]
  PIN la_oenb[85]
    DIRECTION INPUT ;
    USE SIGNAL ;
    PORT
      LAYER met2 ;
        RECT 2105.510 0.000 2105.790 4.000 ;
    END
  END la_oenb[85]
  PIN la_oenb[86]
    DIRECTION INPUT ;
    USE SIGNAL ;
    PORT
      LAYER met2 ;
        RECT 2122.070 0.000 2122.350 4.000 ;
    END
  END la_oenb[86]
  PIN la_oenb[87]
    DIRECTION INPUT ;
    USE SIGNAL ;
    PORT
      LAYER met2 ;
        RECT 2138.630 0.000 2138.910 4.000 ;
    END
  END la_oenb[87]
  PIN la_oenb[88]
    DIRECTION INPUT ;
    USE SIGNAL ;
    PORT
      LAYER met2 ;
        RECT 2155.190 0.000 2155.470 4.000 ;
    END
  END la_oenb[88]
  PIN la_oenb[89]
    DIRECTION INPUT ;
    USE SIGNAL ;
    PORT
      LAYER met2 ;
        RECT 2171.750 0.000 2172.030 4.000 ;
    END
  END la_oenb[89]
  PIN la_oenb[8]
    DIRECTION INPUT ;
    USE SIGNAL ;
    PORT
      LAYER met2 ;
        RECT 830.390 0.000 830.670 4.000 ;
    END
  END la_oenb[8]
  PIN la_oenb[90]
    DIRECTION INPUT ;
    USE SIGNAL ;
    PORT
      LAYER met2 ;
        RECT 2188.310 0.000 2188.590 4.000 ;
    END
  END la_oenb[90]
  PIN la_oenb[91]
    DIRECTION INPUT ;
    USE SIGNAL ;
    PORT
      LAYER met2 ;
        RECT 2204.870 0.000 2205.150 4.000 ;
    END
  END la_oenb[91]
  PIN la_oenb[92]
    DIRECTION INPUT ;
    USE SIGNAL ;
    PORT
      LAYER met2 ;
        RECT 2221.430 0.000 2221.710 4.000 ;
    END
  END la_oenb[92]
  PIN la_oenb[93]
    DIRECTION INPUT ;
    USE SIGNAL ;
    PORT
      LAYER met2 ;
        RECT 2237.990 0.000 2238.270 4.000 ;
    END
  END la_oenb[93]
  PIN la_oenb[94]
    DIRECTION INPUT ;
    USE SIGNAL ;
    PORT
      LAYER met2 ;
        RECT 2254.550 0.000 2254.830 4.000 ;
    END
  END la_oenb[94]
  PIN la_oenb[95]
    DIRECTION INPUT ;
    USE SIGNAL ;
    PORT
      LAYER met2 ;
        RECT 2271.110 0.000 2271.390 4.000 ;
    END
  END la_oenb[95]
  PIN la_oenb[96]
    DIRECTION INPUT ;
    USE SIGNAL ;
    PORT
      LAYER met2 ;
        RECT 2287.670 0.000 2287.950 4.000 ;
    END
  END la_oenb[96]
  PIN la_oenb[97]
    DIRECTION INPUT ;
    USE SIGNAL ;
    PORT
      LAYER met2 ;
        RECT 2304.230 0.000 2304.510 4.000 ;
    END
  END la_oenb[97]
  PIN la_oenb[98]
    DIRECTION INPUT ;
    USE SIGNAL ;
    PORT
      LAYER met2 ;
        RECT 2320.790 0.000 2321.070 4.000 ;
    END
  END la_oenb[98]
  PIN la_oenb[99]
    DIRECTION INPUT ;
    USE SIGNAL ;
    PORT
      LAYER met2 ;
        RECT 2337.350 0.000 2337.630 4.000 ;
    END
  END la_oenb[99]
  PIN la_oenb[9]
    DIRECTION INPUT ;
    USE SIGNAL ;
    PORT
      LAYER met2 ;
        RECT 846.950 0.000 847.230 4.000 ;
    END
  END la_oenb[9]
  PIN vccd1
    DIRECTION INOUT ;
    USE POWER ;
    PORT
      LAYER met4 ;
        RECT 21.040 10.640 22.640 2489.040 ;
    END
    PORT
      LAYER met4 ;
        RECT 174.640 10.640 176.240 2489.040 ;
    END
    PORT
      LAYER met4 ;
        RECT 328.240 10.640 329.840 2489.040 ;
    END
    PORT
      LAYER met4 ;
        RECT 481.840 10.640 483.440 2489.040 ;
    END
    PORT
      LAYER met4 ;
        RECT 635.440 10.640 637.040 2489.040 ;
    END
    PORT
      LAYER met4 ;
        RECT 789.040 10.640 790.640 2489.040 ;
    END
    PORT
      LAYER met4 ;
        RECT 942.640 10.640 944.240 2489.040 ;
    END
    PORT
      LAYER met4 ;
        RECT 1096.240 10.640 1097.840 2489.040 ;
    END
    PORT
      LAYER met4 ;
        RECT 1249.840 10.640 1251.440 2489.040 ;
    END
    PORT
      LAYER met4 ;
        RECT 1403.440 10.640 1405.040 2489.040 ;
    END
    PORT
      LAYER met4 ;
        RECT 1557.040 10.640 1558.640 2489.040 ;
    END
    PORT
      LAYER met4 ;
        RECT 1710.640 10.640 1712.240 2489.040 ;
    END
    PORT
      LAYER met4 ;
        RECT 1864.240 10.640 1865.840 2489.040 ;
    END
    PORT
      LAYER met4 ;
        RECT 2017.840 10.640 2019.440 2489.040 ;
    END
    PORT
      LAYER met4 ;
        RECT 2171.440 10.640 2173.040 2489.040 ;
    END
    PORT
      LAYER met4 ;
        RECT 2325.040 10.640 2326.640 2489.040 ;
    END
    PORT
      LAYER met4 ;
        RECT 2478.640 10.640 2480.240 2489.040 ;
    END
    PORT
      LAYER met4 ;
        RECT 2632.240 10.640 2633.840 2489.040 ;
    END
    PORT
      LAYER met4 ;
        RECT 2785.840 10.640 2787.440 2489.040 ;
    END
  END vccd1
  PIN vssd1
    DIRECTION INOUT ;
    USE GROUND ;
    PORT
      LAYER met4 ;
        RECT 24.340 10.640 25.940 2489.040 ;
    END
    PORT
      LAYER met4 ;
        RECT 177.940 10.640 179.540 2489.040 ;
    END
    PORT
      LAYER met4 ;
        RECT 331.540 10.640 333.140 2489.040 ;
    END
    PORT
      LAYER met4 ;
        RECT 485.140 10.640 486.740 2489.040 ;
    END
    PORT
      LAYER met4 ;
        RECT 638.740 10.640 640.340 2489.040 ;
    END
    PORT
      LAYER met4 ;
        RECT 792.340 10.640 793.940 2489.040 ;
    END
    PORT
      LAYER met4 ;
        RECT 945.940 10.640 947.540 2489.040 ;
    END
    PORT
      LAYER met4 ;
        RECT 1099.540 10.640 1101.140 2489.040 ;
    END
    PORT
      LAYER met4 ;
        RECT 1253.140 10.640 1254.740 2489.040 ;
    END
    PORT
      LAYER met4 ;
        RECT 1406.740 10.640 1408.340 2489.040 ;
    END
    PORT
      LAYER met4 ;
        RECT 1560.340 10.640 1561.940 2489.040 ;
    END
    PORT
      LAYER met4 ;
        RECT 1713.940 10.640 1715.540 2489.040 ;
    END
    PORT
      LAYER met4 ;
        RECT 1867.540 10.640 1869.140 2489.040 ;
    END
    PORT
      LAYER met4 ;
        RECT 2021.140 10.640 2022.740 2489.040 ;
    END
    PORT
      LAYER met4 ;
        RECT 2174.740 10.640 2176.340 2489.040 ;
    END
    PORT
      LAYER met4 ;
        RECT 2328.340 10.640 2329.940 2489.040 ;
    END
    PORT
      LAYER met4 ;
        RECT 2481.940 10.640 2483.540 2489.040 ;
    END
    PORT
      LAYER met4 ;
        RECT 2635.540 10.640 2637.140 2489.040 ;
    END
    PORT
      LAYER met4 ;
        RECT 2789.140 10.640 2790.740 2489.040 ;
    END
  END vssd1
  PIN wb_clk_i
    DIRECTION INPUT ;
    USE SIGNAL ;
    ANTENNAGATEAREA 0.682200 ;
    ANTENNADIFFAREA 0.434700 ;
    PORT
      LAYER met2 ;
        RECT 101.750 0.000 102.030 4.000 ;
    END
  END wb_clk_i
  PIN wb_rst_i
    DIRECTION INPUT ;
    USE SIGNAL ;
    ANTENNAGATEAREA 3.128700 ;
    ANTENNADIFFAREA 0.434700 ;
    PORT
      LAYER met2 ;
        RECT 107.270 0.000 107.550 4.000 ;
    END
  END wb_rst_i
  PIN wbs_ack_o
    DIRECTION OUTPUT ;
    USE SIGNAL ;
    ANTENNADIFFAREA 2.673000 ;
    PORT
      LAYER met2 ;
        RECT 112.790 0.000 113.070 4.000 ;
    END
  END wbs_ack_o
  PIN wbs_adr_i[0]
    DIRECTION INPUT ;
    USE SIGNAL ;
    ANTENNAGATEAREA 0.560700 ;
    ANTENNADIFFAREA 0.434700 ;
    PORT
      LAYER met2 ;
        RECT 134.870 0.000 135.150 4.000 ;
    END
  END wbs_adr_i[0]
  PIN wbs_adr_i[10]
    DIRECTION INPUT ;
    USE SIGNAL ;
    PORT
      LAYER met2 ;
        RECT 322.550 0.000 322.830 4.000 ;
    END
  END wbs_adr_i[10]
  PIN wbs_adr_i[11]
    DIRECTION INPUT ;
    USE SIGNAL ;
    PORT
      LAYER met2 ;
        RECT 339.110 0.000 339.390 4.000 ;
    END
  END wbs_adr_i[11]
  PIN wbs_adr_i[12]
    DIRECTION INPUT ;
    USE SIGNAL ;
    PORT
      LAYER met2 ;
        RECT 355.670 0.000 355.950 4.000 ;
    END
  END wbs_adr_i[12]
  PIN wbs_adr_i[13]
    DIRECTION INPUT ;
    USE SIGNAL ;
    PORT
      LAYER met2 ;
        RECT 372.230 0.000 372.510 4.000 ;
    END
  END wbs_adr_i[13]
  PIN wbs_adr_i[14]
    DIRECTION INPUT ;
    USE SIGNAL ;
    PORT
      LAYER met2 ;
        RECT 388.790 0.000 389.070 4.000 ;
    END
  END wbs_adr_i[14]
  PIN wbs_adr_i[15]
    DIRECTION INPUT ;
    USE SIGNAL ;
    PORT
      LAYER met2 ;
        RECT 405.350 0.000 405.630 4.000 ;
    END
  END wbs_adr_i[15]
  PIN wbs_adr_i[16]
    DIRECTION INPUT ;
    USE SIGNAL ;
    PORT
      LAYER met2 ;
        RECT 421.910 0.000 422.190 4.000 ;
    END
  END wbs_adr_i[16]
  PIN wbs_adr_i[17]
    DIRECTION INPUT ;
    USE SIGNAL ;
    PORT
      LAYER met2 ;
        RECT 438.470 0.000 438.750 4.000 ;
    END
  END wbs_adr_i[17]
  PIN wbs_adr_i[18]
    DIRECTION INPUT ;
    USE SIGNAL ;
    PORT
      LAYER met2 ;
        RECT 455.030 0.000 455.310 4.000 ;
    END
  END wbs_adr_i[18]
  PIN wbs_adr_i[19]
    DIRECTION INPUT ;
    USE SIGNAL ;
    PORT
      LAYER met2 ;
        RECT 471.590 0.000 471.870 4.000 ;
    END
  END wbs_adr_i[19]
  PIN wbs_adr_i[1]
    DIRECTION INPUT ;
    USE SIGNAL ;
    ANTENNAGATEAREA 0.560700 ;
    ANTENNADIFFAREA 0.434700 ;
    PORT
      LAYER met2 ;
        RECT 156.950 0.000 157.230 4.000 ;
    END
  END wbs_adr_i[1]
  PIN wbs_adr_i[20]
    DIRECTION INPUT ;
    USE SIGNAL ;
    PORT
      LAYER met2 ;
        RECT 488.150 0.000 488.430 4.000 ;
    END
  END wbs_adr_i[20]
  PIN wbs_adr_i[21]
    DIRECTION INPUT ;
    USE SIGNAL ;
    PORT
      LAYER met2 ;
        RECT 504.710 0.000 504.990 4.000 ;
    END
  END wbs_adr_i[21]
  PIN wbs_adr_i[22]
    DIRECTION INPUT ;
    USE SIGNAL ;
    PORT
      LAYER met2 ;
        RECT 521.270 0.000 521.550 4.000 ;
    END
  END wbs_adr_i[22]
  PIN wbs_adr_i[23]
    DIRECTION INPUT ;
    USE SIGNAL ;
    PORT
      LAYER met2 ;
        RECT 537.830 0.000 538.110 4.000 ;
    END
  END wbs_adr_i[23]
  PIN wbs_adr_i[24]
    DIRECTION INPUT ;
    USE SIGNAL ;
    PORT
      LAYER met2 ;
        RECT 554.390 0.000 554.670 4.000 ;
    END
  END wbs_adr_i[24]
  PIN wbs_adr_i[25]
    DIRECTION INPUT ;
    USE SIGNAL ;
    PORT
      LAYER met2 ;
        RECT 570.950 0.000 571.230 4.000 ;
    END
  END wbs_adr_i[25]
  PIN wbs_adr_i[26]
    DIRECTION INPUT ;
    USE SIGNAL ;
    PORT
      LAYER met2 ;
        RECT 587.510 0.000 587.790 4.000 ;
    END
  END wbs_adr_i[26]
  PIN wbs_adr_i[27]
    DIRECTION INPUT ;
    USE SIGNAL ;
    PORT
      LAYER met2 ;
        RECT 604.070 0.000 604.350 4.000 ;
    END
  END wbs_adr_i[27]
  PIN wbs_adr_i[28]
    DIRECTION INPUT ;
    USE SIGNAL ;
    PORT
      LAYER met2 ;
        RECT 620.630 0.000 620.910 4.000 ;
    END
  END wbs_adr_i[28]
  PIN wbs_adr_i[29]
    DIRECTION INPUT ;
    USE SIGNAL ;
    PORT
      LAYER met2 ;
        RECT 637.190 0.000 637.470 4.000 ;
    END
  END wbs_adr_i[29]
  PIN wbs_adr_i[2]
    DIRECTION INPUT ;
    USE SIGNAL ;
    ANTENNAGATEAREA 0.560700 ;
    ANTENNADIFFAREA 0.434700 ;
    PORT
      LAYER met2 ;
        RECT 179.030 0.000 179.310 4.000 ;
    END
  END wbs_adr_i[2]
  PIN wbs_adr_i[30]
    DIRECTION INPUT ;
    USE SIGNAL ;
    PORT
      LAYER met2 ;
        RECT 653.750 0.000 654.030 4.000 ;
    END
  END wbs_adr_i[30]
  PIN wbs_adr_i[31]
    DIRECTION INPUT ;
    USE SIGNAL ;
    PORT
      LAYER met2 ;
        RECT 670.310 0.000 670.590 4.000 ;
    END
  END wbs_adr_i[31]
  PIN wbs_adr_i[3]
    DIRECTION INPUT ;
    USE SIGNAL ;
    ANTENNAGATEAREA 0.560700 ;
    ANTENNADIFFAREA 0.434700 ;
    PORT
      LAYER met2 ;
        RECT 201.110 0.000 201.390 4.000 ;
    END
  END wbs_adr_i[3]
  PIN wbs_adr_i[4]
    DIRECTION INPUT ;
    USE SIGNAL ;
    ANTENNAGATEAREA 0.560700 ;
    ANTENNADIFFAREA 0.434700 ;
    PORT
      LAYER met2 ;
        RECT 223.190 0.000 223.470 4.000 ;
    END
  END wbs_adr_i[4]
  PIN wbs_adr_i[5]
    DIRECTION INPUT ;
    USE SIGNAL ;
    ANTENNAGATEAREA 0.560700 ;
    ANTENNADIFFAREA 0.434700 ;
    PORT
      LAYER met2 ;
        RECT 239.750 0.000 240.030 4.000 ;
    END
  END wbs_adr_i[5]
  PIN wbs_adr_i[6]
    DIRECTION INPUT ;
    USE SIGNAL ;
    ANTENNAGATEAREA 0.560700 ;
    ANTENNADIFFAREA 0.434700 ;
    PORT
      LAYER met2 ;
        RECT 256.310 0.000 256.590 4.000 ;
    END
  END wbs_adr_i[6]
  PIN wbs_adr_i[7]
    DIRECTION INPUT ;
    USE SIGNAL ;
    ANTENNAGATEAREA 0.560700 ;
    ANTENNADIFFAREA 0.434700 ;
    PORT
      LAYER met2 ;
        RECT 272.870 0.000 273.150 4.000 ;
    END
  END wbs_adr_i[7]
  PIN wbs_adr_i[8]
    DIRECTION INPUT ;
    USE SIGNAL ;
    PORT
      LAYER met2 ;
        RECT 289.430 0.000 289.710 4.000 ;
    END
  END wbs_adr_i[8]
  PIN wbs_adr_i[9]
    DIRECTION INPUT ;
    USE SIGNAL ;
    PORT
      LAYER met2 ;
        RECT 305.990 0.000 306.270 4.000 ;
    END
  END wbs_adr_i[9]
  PIN wbs_cyc_i
    DIRECTION INPUT ;
    USE SIGNAL ;
    ANTENNAGATEAREA 0.560700 ;
    ANTENNADIFFAREA 0.434700 ;
    PORT
      LAYER met2 ;
        RECT 118.310 0.000 118.590 4.000 ;
    END
  END wbs_cyc_i
  PIN wbs_dat_i[0]
    DIRECTION INPUT ;
    USE SIGNAL ;
    ANTENNAGATEAREA 0.560700 ;
    ANTENNADIFFAREA 0.434700 ;
    PORT
      LAYER met2 ;
        RECT 140.390 0.000 140.670 4.000 ;
    END
  END wbs_dat_i[0]
  PIN wbs_dat_i[10]
    DIRECTION INPUT ;
    USE SIGNAL ;
    ANTENNAGATEAREA 0.560700 ;
    ANTENNADIFFAREA 0.434700 ;
    PORT
      LAYER met2 ;
        RECT 328.070 0.000 328.350 4.000 ;
    END
  END wbs_dat_i[10]
  PIN wbs_dat_i[11]
    DIRECTION INPUT ;
    USE SIGNAL ;
    ANTENNAGATEAREA 0.560700 ;
    ANTENNADIFFAREA 0.434700 ;
    PORT
      LAYER met2 ;
        RECT 344.630 0.000 344.910 4.000 ;
    END
  END wbs_dat_i[11]
  PIN wbs_dat_i[12]
    DIRECTION INPUT ;
    USE SIGNAL ;
    ANTENNAGATEAREA 0.560700 ;
    ANTENNADIFFAREA 0.434700 ;
    PORT
      LAYER met2 ;
        RECT 361.190 0.000 361.470 4.000 ;
    END
  END wbs_dat_i[12]
  PIN wbs_dat_i[13]
    DIRECTION INPUT ;
    USE SIGNAL ;
    ANTENNAGATEAREA 0.560700 ;
    ANTENNADIFFAREA 0.434700 ;
    PORT
      LAYER met2 ;
        RECT 377.750 0.000 378.030 4.000 ;
    END
  END wbs_dat_i[13]
  PIN wbs_dat_i[14]
    DIRECTION INPUT ;
    USE SIGNAL ;
    ANTENNAGATEAREA 0.560700 ;
    ANTENNADIFFAREA 0.434700 ;
    PORT
      LAYER met2 ;
        RECT 394.310 0.000 394.590 4.000 ;
    END
  END wbs_dat_i[14]
  PIN wbs_dat_i[15]
    DIRECTION INPUT ;
    USE SIGNAL ;
    ANTENNAGATEAREA 0.560700 ;
    ANTENNADIFFAREA 0.434700 ;
    PORT
      LAYER met2 ;
        RECT 410.870 0.000 411.150 4.000 ;
    END
  END wbs_dat_i[15]
  PIN wbs_dat_i[16]
    DIRECTION INPUT ;
    USE SIGNAL ;
    PORT
      LAYER met2 ;
        RECT 427.430 0.000 427.710 4.000 ;
    END
  END wbs_dat_i[16]
  PIN wbs_dat_i[17]
    DIRECTION INPUT ;
    USE SIGNAL ;
    PORT
      LAYER met2 ;
        RECT 443.990 0.000 444.270 4.000 ;
    END
  END wbs_dat_i[17]
  PIN wbs_dat_i[18]
    DIRECTION INPUT ;
    USE SIGNAL ;
    PORT
      LAYER met2 ;
        RECT 460.550 0.000 460.830 4.000 ;
    END
  END wbs_dat_i[18]
  PIN wbs_dat_i[19]
    DIRECTION INPUT ;
    USE SIGNAL ;
    PORT
      LAYER met2 ;
        RECT 477.110 0.000 477.390 4.000 ;
    END
  END wbs_dat_i[19]
  PIN wbs_dat_i[1]
    DIRECTION INPUT ;
    USE SIGNAL ;
    ANTENNAGATEAREA 0.560700 ;
    ANTENNADIFFAREA 0.434700 ;
    PORT
      LAYER met2 ;
        RECT 162.470 0.000 162.750 4.000 ;
    END
  END wbs_dat_i[1]
  PIN wbs_dat_i[20]
    DIRECTION INPUT ;
    USE SIGNAL ;
    PORT
      LAYER met2 ;
        RECT 493.670 0.000 493.950 4.000 ;
    END
  END wbs_dat_i[20]
  PIN wbs_dat_i[21]
    DIRECTION INPUT ;
    USE SIGNAL ;
    PORT
      LAYER met2 ;
        RECT 510.230 0.000 510.510 4.000 ;
    END
  END wbs_dat_i[21]
  PIN wbs_dat_i[22]
    DIRECTION INPUT ;
    USE SIGNAL ;
    PORT
      LAYER met2 ;
        RECT 526.790 0.000 527.070 4.000 ;
    END
  END wbs_dat_i[22]
  PIN wbs_dat_i[23]
    DIRECTION INPUT ;
    USE SIGNAL ;
    PORT
      LAYER met2 ;
        RECT 543.350 0.000 543.630 4.000 ;
    END
  END wbs_dat_i[23]
  PIN wbs_dat_i[24]
    DIRECTION INPUT ;
    USE SIGNAL ;
    PORT
      LAYER met2 ;
        RECT 559.910 0.000 560.190 4.000 ;
    END
  END wbs_dat_i[24]
  PIN wbs_dat_i[25]
    DIRECTION INPUT ;
    USE SIGNAL ;
    PORT
      LAYER met2 ;
        RECT 576.470 0.000 576.750 4.000 ;
    END
  END wbs_dat_i[25]
  PIN wbs_dat_i[26]
    DIRECTION INPUT ;
    USE SIGNAL ;
    PORT
      LAYER met2 ;
        RECT 593.030 0.000 593.310 4.000 ;
    END
  END wbs_dat_i[26]
  PIN wbs_dat_i[27]
    DIRECTION INPUT ;
    USE SIGNAL ;
    PORT
      LAYER met2 ;
        RECT 609.590 0.000 609.870 4.000 ;
    END
  END wbs_dat_i[27]
  PIN wbs_dat_i[28]
    DIRECTION INPUT ;
    USE SIGNAL ;
    PORT
      LAYER met2 ;
        RECT 626.150 0.000 626.430 4.000 ;
    END
  END wbs_dat_i[28]
  PIN wbs_dat_i[29]
    DIRECTION INPUT ;
    USE SIGNAL ;
    PORT
      LAYER met2 ;
        RECT 642.710 0.000 642.990 4.000 ;
    END
  END wbs_dat_i[29]
  PIN wbs_dat_i[2]
    DIRECTION INPUT ;
    USE SIGNAL ;
    ANTENNAGATEAREA 0.560700 ;
    ANTENNADIFFAREA 0.434700 ;
    PORT
      LAYER met2 ;
        RECT 184.550 0.000 184.830 4.000 ;
    END
  END wbs_dat_i[2]
  PIN wbs_dat_i[30]
    DIRECTION INPUT ;
    USE SIGNAL ;
    PORT
      LAYER met2 ;
        RECT 659.270 0.000 659.550 4.000 ;
    END
  END wbs_dat_i[30]
  PIN wbs_dat_i[31]
    DIRECTION INPUT ;
    USE SIGNAL ;
    PORT
      LAYER met2 ;
        RECT 675.830 0.000 676.110 4.000 ;
    END
  END wbs_dat_i[31]
  PIN wbs_dat_i[3]
    DIRECTION INPUT ;
    USE SIGNAL ;
    ANTENNAGATEAREA 0.560700 ;
    ANTENNADIFFAREA 0.434700 ;
    PORT
      LAYER met2 ;
        RECT 206.630 0.000 206.910 4.000 ;
    END
  END wbs_dat_i[3]
  PIN wbs_dat_i[4]
    DIRECTION INPUT ;
    USE SIGNAL ;
    ANTENNAGATEAREA 0.560700 ;
    ANTENNADIFFAREA 0.434700 ;
    PORT
      LAYER met2 ;
        RECT 228.710 0.000 228.990 4.000 ;
    END
  END wbs_dat_i[4]
  PIN wbs_dat_i[5]
    DIRECTION INPUT ;
    USE SIGNAL ;
    ANTENNAGATEAREA 0.560700 ;
    ANTENNADIFFAREA 0.434700 ;
    PORT
      LAYER met2 ;
        RECT 245.270 0.000 245.550 4.000 ;
    END
  END wbs_dat_i[5]
  PIN wbs_dat_i[6]
    DIRECTION INPUT ;
    USE SIGNAL ;
    ANTENNAGATEAREA 0.560700 ;
    ANTENNADIFFAREA 0.434700 ;
    PORT
      LAYER met2 ;
        RECT 261.830 0.000 262.110 4.000 ;
    END
  END wbs_dat_i[6]
  PIN wbs_dat_i[7]
    DIRECTION INPUT ;
    USE SIGNAL ;
    ANTENNAGATEAREA 0.560700 ;
    ANTENNADIFFAREA 0.434700 ;
    PORT
      LAYER met2 ;
        RECT 278.390 0.000 278.670 4.000 ;
    END
  END wbs_dat_i[7]
  PIN wbs_dat_i[8]
    DIRECTION INPUT ;
    USE SIGNAL ;
    ANTENNAGATEAREA 0.560700 ;
    ANTENNADIFFAREA 0.434700 ;
    PORT
      LAYER met2 ;
        RECT 294.950 0.000 295.230 4.000 ;
    END
  END wbs_dat_i[8]
  PIN wbs_dat_i[9]
    DIRECTION INPUT ;
    USE SIGNAL ;
    ANTENNAGATEAREA 0.560700 ;
    ANTENNADIFFAREA 0.434700 ;
    PORT
      LAYER met2 ;
        RECT 311.510 0.000 311.790 4.000 ;
    END
  END wbs_dat_i[9]
  PIN wbs_dat_o[0]
    DIRECTION OUTPUT ;
    USE SIGNAL ;
    ANTENNADIFFAREA 2.673000 ;
    PORT
      LAYER met2 ;
        RECT 145.910 0.000 146.190 4.000 ;
    END
  END wbs_dat_o[0]
  PIN wbs_dat_o[10]
    DIRECTION OUTPUT ;
    USE SIGNAL ;
    ANTENNADIFFAREA 2.673000 ;
    PORT
      LAYER met2 ;
        RECT 333.590 0.000 333.870 4.000 ;
    END
  END wbs_dat_o[10]
  PIN wbs_dat_o[11]
    DIRECTION OUTPUT ;
    USE SIGNAL ;
    ANTENNADIFFAREA 2.673000 ;
    PORT
      LAYER met2 ;
        RECT 350.150 0.000 350.430 4.000 ;
    END
  END wbs_dat_o[11]
  PIN wbs_dat_o[12]
    DIRECTION OUTPUT ;
    USE SIGNAL ;
    ANTENNADIFFAREA 2.673000 ;
    PORT
      LAYER met2 ;
        RECT 366.710 0.000 366.990 4.000 ;
    END
  END wbs_dat_o[12]
  PIN wbs_dat_o[13]
    DIRECTION OUTPUT ;
    USE SIGNAL ;
    ANTENNADIFFAREA 2.673000 ;
    PORT
      LAYER met2 ;
        RECT 383.270 0.000 383.550 4.000 ;
    END
  END wbs_dat_o[13]
  PIN wbs_dat_o[14]
    DIRECTION OUTPUT ;
    USE SIGNAL ;
    ANTENNADIFFAREA 2.673000 ;
    PORT
      LAYER met2 ;
        RECT 399.830 0.000 400.110 4.000 ;
    END
  END wbs_dat_o[14]
  PIN wbs_dat_o[15]
    DIRECTION OUTPUT ;
    USE SIGNAL ;
    ANTENNADIFFAREA 2.673000 ;
    PORT
      LAYER met2 ;
        RECT 416.390 0.000 416.670 4.000 ;
    END
  END wbs_dat_o[15]
  PIN wbs_dat_o[16]
    DIRECTION OUTPUT ;
    USE SIGNAL ;
    PORT
      LAYER met2 ;
        RECT 432.950 0.000 433.230 4.000 ;
    END
  END wbs_dat_o[16]
  PIN wbs_dat_o[17]
    DIRECTION OUTPUT ;
    USE SIGNAL ;
    PORT
      LAYER met2 ;
        RECT 449.510 0.000 449.790 4.000 ;
    END
  END wbs_dat_o[17]
  PIN wbs_dat_o[18]
    DIRECTION OUTPUT ;
    USE SIGNAL ;
    PORT
      LAYER met2 ;
        RECT 466.070 0.000 466.350 4.000 ;
    END
  END wbs_dat_o[18]
  PIN wbs_dat_o[19]
    DIRECTION OUTPUT ;
    USE SIGNAL ;
    PORT
      LAYER met2 ;
        RECT 482.630 0.000 482.910 4.000 ;
    END
  END wbs_dat_o[19]
  PIN wbs_dat_o[1]
    DIRECTION OUTPUT ;
    USE SIGNAL ;
    ANTENNADIFFAREA 2.673000 ;
    PORT
      LAYER met2 ;
        RECT 167.990 0.000 168.270 4.000 ;
    END
  END wbs_dat_o[1]
  PIN wbs_dat_o[20]
    DIRECTION OUTPUT ;
    USE SIGNAL ;
    PORT
      LAYER met2 ;
        RECT 499.190 0.000 499.470 4.000 ;
    END
  END wbs_dat_o[20]
  PIN wbs_dat_o[21]
    DIRECTION OUTPUT ;
    USE SIGNAL ;
    PORT
      LAYER met2 ;
        RECT 515.750 0.000 516.030 4.000 ;
    END
  END wbs_dat_o[21]
  PIN wbs_dat_o[22]
    DIRECTION OUTPUT ;
    USE SIGNAL ;
    PORT
      LAYER met2 ;
        RECT 532.310 0.000 532.590 4.000 ;
    END
  END wbs_dat_o[22]
  PIN wbs_dat_o[23]
    DIRECTION OUTPUT ;
    USE SIGNAL ;
    PORT
      LAYER met2 ;
        RECT 548.870 0.000 549.150 4.000 ;
    END
  END wbs_dat_o[23]
  PIN wbs_dat_o[24]
    DIRECTION OUTPUT ;
    USE SIGNAL ;
    PORT
      LAYER met2 ;
        RECT 565.430 0.000 565.710 4.000 ;
    END
  END wbs_dat_o[24]
  PIN wbs_dat_o[25]
    DIRECTION OUTPUT ;
    USE SIGNAL ;
    PORT
      LAYER met2 ;
        RECT 581.990 0.000 582.270 4.000 ;
    END
  END wbs_dat_o[25]
  PIN wbs_dat_o[26]
    DIRECTION OUTPUT ;
    USE SIGNAL ;
    PORT
      LAYER met2 ;
        RECT 598.550 0.000 598.830 4.000 ;
    END
  END wbs_dat_o[26]
  PIN wbs_dat_o[27]
    DIRECTION OUTPUT ;
    USE SIGNAL ;
    PORT
      LAYER met2 ;
        RECT 615.110 0.000 615.390 4.000 ;
    END
  END wbs_dat_o[27]
  PIN wbs_dat_o[28]
    DIRECTION OUTPUT ;
    USE SIGNAL ;
    PORT
      LAYER met2 ;
        RECT 631.670 0.000 631.950 4.000 ;
    END
  END wbs_dat_o[28]
  PIN wbs_dat_o[29]
    DIRECTION OUTPUT ;
    USE SIGNAL ;
    PORT
      LAYER met2 ;
        RECT 648.230 0.000 648.510 4.000 ;
    END
  END wbs_dat_o[29]
  PIN wbs_dat_o[2]
    DIRECTION OUTPUT ;
    USE SIGNAL ;
    ANTENNADIFFAREA 2.673000 ;
    PORT
      LAYER met2 ;
        RECT 190.070 0.000 190.350 4.000 ;
    END
  END wbs_dat_o[2]
  PIN wbs_dat_o[30]
    DIRECTION OUTPUT ;
    USE SIGNAL ;
    PORT
      LAYER met2 ;
        RECT 664.790 0.000 665.070 4.000 ;
    END
  END wbs_dat_o[30]
  PIN wbs_dat_o[31]
    DIRECTION OUTPUT ;
    USE SIGNAL ;
    PORT
      LAYER met2 ;
        RECT 681.350 0.000 681.630 4.000 ;
    END
  END wbs_dat_o[31]
  PIN wbs_dat_o[3]
    DIRECTION OUTPUT ;
    USE SIGNAL ;
    ANTENNADIFFAREA 2.673000 ;
    PORT
      LAYER met2 ;
        RECT 212.150 0.000 212.430 4.000 ;
    END
  END wbs_dat_o[3]
  PIN wbs_dat_o[4]
    DIRECTION OUTPUT ;
    USE SIGNAL ;
    ANTENNADIFFAREA 2.673000 ;
    PORT
      LAYER met2 ;
        RECT 234.230 0.000 234.510 4.000 ;
    END
  END wbs_dat_o[4]
  PIN wbs_dat_o[5]
    DIRECTION OUTPUT ;
    USE SIGNAL ;
    ANTENNADIFFAREA 2.673000 ;
    PORT
      LAYER met2 ;
        RECT 250.790 0.000 251.070 4.000 ;
    END
  END wbs_dat_o[5]
  PIN wbs_dat_o[6]
    DIRECTION OUTPUT ;
    USE SIGNAL ;
    ANTENNADIFFAREA 2.673000 ;
    PORT
      LAYER met2 ;
        RECT 267.350 0.000 267.630 4.000 ;
    END
  END wbs_dat_o[6]
  PIN wbs_dat_o[7]
    DIRECTION OUTPUT ;
    USE SIGNAL ;
    ANTENNADIFFAREA 2.673000 ;
    PORT
      LAYER met2 ;
        RECT 283.910 0.000 284.190 4.000 ;
    END
  END wbs_dat_o[7]
  PIN wbs_dat_o[8]
    DIRECTION OUTPUT ;
    USE SIGNAL ;
    ANTENNADIFFAREA 2.673000 ;
    PORT
      LAYER met2 ;
        RECT 300.470 0.000 300.750 4.000 ;
    END
  END wbs_dat_o[8]
  PIN wbs_dat_o[9]
    DIRECTION OUTPUT ;
    USE SIGNAL ;
    ANTENNADIFFAREA 2.673000 ;
    PORT
      LAYER met2 ;
        RECT 317.030 0.000 317.310 4.000 ;
    END
  END wbs_dat_o[9]
  PIN wbs_sel_i[0]
    DIRECTION INPUT ;
    USE SIGNAL ;
    ANTENNAGATEAREA 0.560700 ;
    ANTENNADIFFAREA 0.434700 ;
    PORT
      LAYER met2 ;
        RECT 151.430 0.000 151.710 4.000 ;
    END
  END wbs_sel_i[0]
  PIN wbs_sel_i[1]
    DIRECTION INPUT ;
    USE SIGNAL ;
    ANTENNAGATEAREA 0.560700 ;
    ANTENNADIFFAREA 0.434700 ;
    PORT
      LAYER met2 ;
        RECT 173.510 0.000 173.790 4.000 ;
    END
  END wbs_sel_i[1]
  PIN wbs_sel_i[2]
    DIRECTION INPUT ;
    USE SIGNAL ;
    PORT
      LAYER met2 ;
        RECT 195.590 0.000 195.870 4.000 ;
    END
  END wbs_sel_i[2]
  PIN wbs_sel_i[3]
    DIRECTION INPUT ;
    USE SIGNAL ;
    PORT
      LAYER met2 ;
        RECT 217.670 0.000 217.950 4.000 ;
    END
  END wbs_sel_i[3]
  PIN wbs_stb_i
    DIRECTION INPUT ;
    USE SIGNAL ;
    ANTENNAGATEAREA 0.560700 ;
    ANTENNADIFFAREA 0.434700 ;
    PORT
      LAYER met2 ;
        RECT 123.830 0.000 124.110 4.000 ;
    END
  END wbs_stb_i
  PIN wbs_we_i
    DIRECTION INPUT ;
    USE SIGNAL ;
    ANTENNAGATEAREA 0.560700 ;
    ANTENNADIFFAREA 0.434700 ;
    PORT
      LAYER met2 ;
        RECT 129.350 0.000 129.630 4.000 ;
    END
  END wbs_we_i
  OBS
      LAYER nwell ;
        RECT 5.330 10.795 2914.290 2488.990 ;
      LAYER li1 ;
        RECT 5.520 10.795 2914.100 2488.885 ;
      LAYER met1 ;
        RECT 4.210 0.380 2914.100 2489.040 ;
      LAYER met2 ;
        RECT 4.230 4.280 2912.170 2488.985 ;
        RECT 4.230 0.350 101.470 4.280 ;
        RECT 102.310 0.350 106.990 4.280 ;
        RECT 107.830 0.350 112.510 4.280 ;
        RECT 113.350 0.350 118.030 4.280 ;
        RECT 118.870 0.350 123.550 4.280 ;
        RECT 124.390 0.350 129.070 4.280 ;
        RECT 129.910 0.350 134.590 4.280 ;
        RECT 135.430 0.350 140.110 4.280 ;
        RECT 140.950 0.350 145.630 4.280 ;
        RECT 146.470 0.350 151.150 4.280 ;
        RECT 151.990 0.350 156.670 4.280 ;
        RECT 157.510 0.350 162.190 4.280 ;
        RECT 163.030 0.350 167.710 4.280 ;
        RECT 168.550 0.350 173.230 4.280 ;
        RECT 174.070 0.350 178.750 4.280 ;
        RECT 179.590 0.350 184.270 4.280 ;
        RECT 185.110 0.350 189.790 4.280 ;
        RECT 190.630 0.350 195.310 4.280 ;
        RECT 196.150 0.350 200.830 4.280 ;
        RECT 201.670 0.350 206.350 4.280 ;
        RECT 207.190 0.350 211.870 4.280 ;
        RECT 212.710 0.350 217.390 4.280 ;
        RECT 218.230 0.350 222.910 4.280 ;
        RECT 223.750 0.350 228.430 4.280 ;
        RECT 229.270 0.350 233.950 4.280 ;
        RECT 234.790 0.350 239.470 4.280 ;
        RECT 240.310 0.350 244.990 4.280 ;
        RECT 245.830 0.350 250.510 4.280 ;
        RECT 251.350 0.350 256.030 4.280 ;
        RECT 256.870 0.350 261.550 4.280 ;
        RECT 262.390 0.350 267.070 4.280 ;
        RECT 267.910 0.350 272.590 4.280 ;
        RECT 273.430 0.350 278.110 4.280 ;
        RECT 278.950 0.350 283.630 4.280 ;
        RECT 284.470 0.350 289.150 4.280 ;
        RECT 289.990 0.350 294.670 4.280 ;
        RECT 295.510 0.350 300.190 4.280 ;
        RECT 301.030 0.350 305.710 4.280 ;
        RECT 306.550 0.350 311.230 4.280 ;
        RECT 312.070 0.350 316.750 4.280 ;
        RECT 317.590 0.350 322.270 4.280 ;
        RECT 323.110 0.350 327.790 4.280 ;
        RECT 328.630 0.350 333.310 4.280 ;
        RECT 334.150 0.350 338.830 4.280 ;
        RECT 339.670 0.350 344.350 4.280 ;
        RECT 345.190 0.350 349.870 4.280 ;
        RECT 350.710 0.350 355.390 4.280 ;
        RECT 356.230 0.350 360.910 4.280 ;
        RECT 361.750 0.350 366.430 4.280 ;
        RECT 367.270 0.350 371.950 4.280 ;
        RECT 372.790 0.350 377.470 4.280 ;
        RECT 378.310 0.350 382.990 4.280 ;
        RECT 383.830 0.350 388.510 4.280 ;
        RECT 389.350 0.350 394.030 4.280 ;
        RECT 394.870 0.350 399.550 4.280 ;
        RECT 400.390 0.350 405.070 4.280 ;
        RECT 405.910 0.350 410.590 4.280 ;
        RECT 411.430 0.350 416.110 4.280 ;
        RECT 416.950 0.350 421.630 4.280 ;
        RECT 422.470 0.350 427.150 4.280 ;
        RECT 427.990 0.350 432.670 4.280 ;
        RECT 433.510 0.350 438.190 4.280 ;
        RECT 439.030 0.350 443.710 4.280 ;
        RECT 444.550 0.350 449.230 4.280 ;
        RECT 450.070 0.350 454.750 4.280 ;
        RECT 455.590 0.350 460.270 4.280 ;
        RECT 461.110 0.350 465.790 4.280 ;
        RECT 466.630 0.350 471.310 4.280 ;
        RECT 472.150 0.350 476.830 4.280 ;
        RECT 477.670 0.350 482.350 4.280 ;
        RECT 483.190 0.350 487.870 4.280 ;
        RECT 488.710 0.350 493.390 4.280 ;
        RECT 494.230 0.350 498.910 4.280 ;
        RECT 499.750 0.350 504.430 4.280 ;
        RECT 505.270 0.350 509.950 4.280 ;
        RECT 510.790 0.350 515.470 4.280 ;
        RECT 516.310 0.350 520.990 4.280 ;
        RECT 521.830 0.350 526.510 4.280 ;
        RECT 527.350 0.350 532.030 4.280 ;
        RECT 532.870 0.350 537.550 4.280 ;
        RECT 538.390 0.350 543.070 4.280 ;
        RECT 543.910 0.350 548.590 4.280 ;
        RECT 549.430 0.350 554.110 4.280 ;
        RECT 554.950 0.350 559.630 4.280 ;
        RECT 560.470 0.350 565.150 4.280 ;
        RECT 565.990 0.350 570.670 4.280 ;
        RECT 571.510 0.350 576.190 4.280 ;
        RECT 577.030 0.350 581.710 4.280 ;
        RECT 582.550 0.350 587.230 4.280 ;
        RECT 588.070 0.350 592.750 4.280 ;
        RECT 593.590 0.350 598.270 4.280 ;
        RECT 599.110 0.350 603.790 4.280 ;
        RECT 604.630 0.350 609.310 4.280 ;
        RECT 610.150 0.350 614.830 4.280 ;
        RECT 615.670 0.350 620.350 4.280 ;
        RECT 621.190 0.350 625.870 4.280 ;
        RECT 626.710 0.350 631.390 4.280 ;
        RECT 632.230 0.350 636.910 4.280 ;
        RECT 637.750 0.350 642.430 4.280 ;
        RECT 643.270 0.350 647.950 4.280 ;
        RECT 648.790 0.350 653.470 4.280 ;
        RECT 654.310 0.350 658.990 4.280 ;
        RECT 659.830 0.350 664.510 4.280 ;
        RECT 665.350 0.350 670.030 4.280 ;
        RECT 670.870 0.350 675.550 4.280 ;
        RECT 676.390 0.350 681.070 4.280 ;
        RECT 681.910 0.350 686.590 4.280 ;
        RECT 687.430 0.350 692.110 4.280 ;
        RECT 692.950 0.350 697.630 4.280 ;
        RECT 698.470 0.350 703.150 4.280 ;
        RECT 703.990 0.350 708.670 4.280 ;
        RECT 709.510 0.350 714.190 4.280 ;
        RECT 715.030 0.350 719.710 4.280 ;
        RECT 720.550 0.350 725.230 4.280 ;
        RECT 726.070 0.350 730.750 4.280 ;
        RECT 731.590 0.350 736.270 4.280 ;
        RECT 737.110 0.350 741.790 4.280 ;
        RECT 742.630 0.350 747.310 4.280 ;
        RECT 748.150 0.350 752.830 4.280 ;
        RECT 753.670 0.350 758.350 4.280 ;
        RECT 759.190 0.350 763.870 4.280 ;
        RECT 764.710 0.350 769.390 4.280 ;
        RECT 770.230 0.350 774.910 4.280 ;
        RECT 775.750 0.350 780.430 4.280 ;
        RECT 781.270 0.350 785.950 4.280 ;
        RECT 786.790 0.350 791.470 4.280 ;
        RECT 792.310 0.350 796.990 4.280 ;
        RECT 797.830 0.350 802.510 4.280 ;
        RECT 803.350 0.350 808.030 4.280 ;
        RECT 808.870 0.350 813.550 4.280 ;
        RECT 814.390 0.350 819.070 4.280 ;
        RECT 819.910 0.350 824.590 4.280 ;
        RECT 825.430 0.350 830.110 4.280 ;
        RECT 830.950 0.350 835.630 4.280 ;
        RECT 836.470 0.350 841.150 4.280 ;
        RECT 841.990 0.350 846.670 4.280 ;
        RECT 847.510 0.350 852.190 4.280 ;
        RECT 853.030 0.350 857.710 4.280 ;
        RECT 858.550 0.350 863.230 4.280 ;
        RECT 864.070 0.350 868.750 4.280 ;
        RECT 869.590 0.350 874.270 4.280 ;
        RECT 875.110 0.350 879.790 4.280 ;
        RECT 880.630 0.350 885.310 4.280 ;
        RECT 886.150 0.350 890.830 4.280 ;
        RECT 891.670 0.350 896.350 4.280 ;
        RECT 897.190 0.350 901.870 4.280 ;
        RECT 902.710 0.350 907.390 4.280 ;
        RECT 908.230 0.350 912.910 4.280 ;
        RECT 913.750 0.350 918.430 4.280 ;
        RECT 919.270 0.350 923.950 4.280 ;
        RECT 924.790 0.350 929.470 4.280 ;
        RECT 930.310 0.350 934.990 4.280 ;
        RECT 935.830 0.350 940.510 4.280 ;
        RECT 941.350 0.350 946.030 4.280 ;
        RECT 946.870 0.350 951.550 4.280 ;
        RECT 952.390 0.350 957.070 4.280 ;
        RECT 957.910 0.350 962.590 4.280 ;
        RECT 963.430 0.350 968.110 4.280 ;
        RECT 968.950 0.350 973.630 4.280 ;
        RECT 974.470 0.350 979.150 4.280 ;
        RECT 979.990 0.350 984.670 4.280 ;
        RECT 985.510 0.350 990.190 4.280 ;
        RECT 991.030 0.350 995.710 4.280 ;
        RECT 996.550 0.350 1001.230 4.280 ;
        RECT 1002.070 0.350 1006.750 4.280 ;
        RECT 1007.590 0.350 1012.270 4.280 ;
        RECT 1013.110 0.350 1017.790 4.280 ;
        RECT 1018.630 0.350 1023.310 4.280 ;
        RECT 1024.150 0.350 1028.830 4.280 ;
        RECT 1029.670 0.350 1034.350 4.280 ;
        RECT 1035.190 0.350 1039.870 4.280 ;
        RECT 1040.710 0.350 1045.390 4.280 ;
        RECT 1046.230 0.350 1050.910 4.280 ;
        RECT 1051.750 0.350 1056.430 4.280 ;
        RECT 1057.270 0.350 1061.950 4.280 ;
        RECT 1062.790 0.350 1067.470 4.280 ;
        RECT 1068.310 0.350 1072.990 4.280 ;
        RECT 1073.830 0.350 1078.510 4.280 ;
        RECT 1079.350 0.350 1084.030 4.280 ;
        RECT 1084.870 0.350 1089.550 4.280 ;
        RECT 1090.390 0.350 1095.070 4.280 ;
        RECT 1095.910 0.350 1100.590 4.280 ;
        RECT 1101.430 0.350 1106.110 4.280 ;
        RECT 1106.950 0.350 1111.630 4.280 ;
        RECT 1112.470 0.350 1117.150 4.280 ;
        RECT 1117.990 0.350 1122.670 4.280 ;
        RECT 1123.510 0.350 1128.190 4.280 ;
        RECT 1129.030 0.350 1133.710 4.280 ;
        RECT 1134.550 0.350 1139.230 4.280 ;
        RECT 1140.070 0.350 1144.750 4.280 ;
        RECT 1145.590 0.350 1150.270 4.280 ;
        RECT 1151.110 0.350 1155.790 4.280 ;
        RECT 1156.630 0.350 1161.310 4.280 ;
        RECT 1162.150 0.350 1166.830 4.280 ;
        RECT 1167.670 0.350 1172.350 4.280 ;
        RECT 1173.190 0.350 1177.870 4.280 ;
        RECT 1178.710 0.350 1183.390 4.280 ;
        RECT 1184.230 0.350 1188.910 4.280 ;
        RECT 1189.750 0.350 1194.430 4.280 ;
        RECT 1195.270 0.350 1199.950 4.280 ;
        RECT 1200.790 0.350 1205.470 4.280 ;
        RECT 1206.310 0.350 1210.990 4.280 ;
        RECT 1211.830 0.350 1216.510 4.280 ;
        RECT 1217.350 0.350 1222.030 4.280 ;
        RECT 1222.870 0.350 1227.550 4.280 ;
        RECT 1228.390 0.350 1233.070 4.280 ;
        RECT 1233.910 0.350 1238.590 4.280 ;
        RECT 1239.430 0.350 1244.110 4.280 ;
        RECT 1244.950 0.350 1249.630 4.280 ;
        RECT 1250.470 0.350 1255.150 4.280 ;
        RECT 1255.990 0.350 1260.670 4.280 ;
        RECT 1261.510 0.350 1266.190 4.280 ;
        RECT 1267.030 0.350 1271.710 4.280 ;
        RECT 1272.550 0.350 1277.230 4.280 ;
        RECT 1278.070 0.350 1282.750 4.280 ;
        RECT 1283.590 0.350 1288.270 4.280 ;
        RECT 1289.110 0.350 1293.790 4.280 ;
        RECT 1294.630 0.350 1299.310 4.280 ;
        RECT 1300.150 0.350 1304.830 4.280 ;
        RECT 1305.670 0.350 1310.350 4.280 ;
        RECT 1311.190 0.350 1315.870 4.280 ;
        RECT 1316.710 0.350 1321.390 4.280 ;
        RECT 1322.230 0.350 1326.910 4.280 ;
        RECT 1327.750 0.350 1332.430 4.280 ;
        RECT 1333.270 0.350 1337.950 4.280 ;
        RECT 1338.790 0.350 1343.470 4.280 ;
        RECT 1344.310 0.350 1348.990 4.280 ;
        RECT 1349.830 0.350 1354.510 4.280 ;
        RECT 1355.350 0.350 1360.030 4.280 ;
        RECT 1360.870 0.350 1365.550 4.280 ;
        RECT 1366.390 0.350 1371.070 4.280 ;
        RECT 1371.910 0.350 1376.590 4.280 ;
        RECT 1377.430 0.350 1382.110 4.280 ;
        RECT 1382.950 0.350 1387.630 4.280 ;
        RECT 1388.470 0.350 1393.150 4.280 ;
        RECT 1393.990 0.350 1398.670 4.280 ;
        RECT 1399.510 0.350 1404.190 4.280 ;
        RECT 1405.030 0.350 1409.710 4.280 ;
        RECT 1410.550 0.350 1415.230 4.280 ;
        RECT 1416.070 0.350 1420.750 4.280 ;
        RECT 1421.590 0.350 1426.270 4.280 ;
        RECT 1427.110 0.350 1431.790 4.280 ;
        RECT 1432.630 0.350 1437.310 4.280 ;
        RECT 1438.150 0.350 1442.830 4.280 ;
        RECT 1443.670 0.350 1448.350 4.280 ;
        RECT 1449.190 0.350 1453.870 4.280 ;
        RECT 1454.710 0.350 1459.390 4.280 ;
        RECT 1460.230 0.350 1464.910 4.280 ;
        RECT 1465.750 0.350 1470.430 4.280 ;
        RECT 1471.270 0.350 1475.950 4.280 ;
        RECT 1476.790 0.350 1481.470 4.280 ;
        RECT 1482.310 0.350 1486.990 4.280 ;
        RECT 1487.830 0.350 1492.510 4.280 ;
        RECT 1493.350 0.350 1498.030 4.280 ;
        RECT 1498.870 0.350 1503.550 4.280 ;
        RECT 1504.390 0.350 1509.070 4.280 ;
        RECT 1509.910 0.350 1514.590 4.280 ;
        RECT 1515.430 0.350 1520.110 4.280 ;
        RECT 1520.950 0.350 1525.630 4.280 ;
        RECT 1526.470 0.350 1531.150 4.280 ;
        RECT 1531.990 0.350 1536.670 4.280 ;
        RECT 1537.510 0.350 1542.190 4.280 ;
        RECT 1543.030 0.350 1547.710 4.280 ;
        RECT 1548.550 0.350 1553.230 4.280 ;
        RECT 1554.070 0.350 1558.750 4.280 ;
        RECT 1559.590 0.350 1564.270 4.280 ;
        RECT 1565.110 0.350 1569.790 4.280 ;
        RECT 1570.630 0.350 1575.310 4.280 ;
        RECT 1576.150 0.350 1580.830 4.280 ;
        RECT 1581.670 0.350 1586.350 4.280 ;
        RECT 1587.190 0.350 1591.870 4.280 ;
        RECT 1592.710 0.350 1597.390 4.280 ;
        RECT 1598.230 0.350 1602.910 4.280 ;
        RECT 1603.750 0.350 1608.430 4.280 ;
        RECT 1609.270 0.350 1613.950 4.280 ;
        RECT 1614.790 0.350 1619.470 4.280 ;
        RECT 1620.310 0.350 1624.990 4.280 ;
        RECT 1625.830 0.350 1630.510 4.280 ;
        RECT 1631.350 0.350 1636.030 4.280 ;
        RECT 1636.870 0.350 1641.550 4.280 ;
        RECT 1642.390 0.350 1647.070 4.280 ;
        RECT 1647.910 0.350 1652.590 4.280 ;
        RECT 1653.430 0.350 1658.110 4.280 ;
        RECT 1658.950 0.350 1663.630 4.280 ;
        RECT 1664.470 0.350 1669.150 4.280 ;
        RECT 1669.990 0.350 1674.670 4.280 ;
        RECT 1675.510 0.350 1680.190 4.280 ;
        RECT 1681.030 0.350 1685.710 4.280 ;
        RECT 1686.550 0.350 1691.230 4.280 ;
        RECT 1692.070 0.350 1696.750 4.280 ;
        RECT 1697.590 0.350 1702.270 4.280 ;
        RECT 1703.110 0.350 1707.790 4.280 ;
        RECT 1708.630 0.350 1713.310 4.280 ;
        RECT 1714.150 0.350 1718.830 4.280 ;
        RECT 1719.670 0.350 1724.350 4.280 ;
        RECT 1725.190 0.350 1729.870 4.280 ;
        RECT 1730.710 0.350 1735.390 4.280 ;
        RECT 1736.230 0.350 1740.910 4.280 ;
        RECT 1741.750 0.350 1746.430 4.280 ;
        RECT 1747.270 0.350 1751.950 4.280 ;
        RECT 1752.790 0.350 1757.470 4.280 ;
        RECT 1758.310 0.350 1762.990 4.280 ;
        RECT 1763.830 0.350 1768.510 4.280 ;
        RECT 1769.350 0.350 1774.030 4.280 ;
        RECT 1774.870 0.350 1779.550 4.280 ;
        RECT 1780.390 0.350 1785.070 4.280 ;
        RECT 1785.910 0.350 1790.590 4.280 ;
        RECT 1791.430 0.350 1796.110 4.280 ;
        RECT 1796.950 0.350 1801.630 4.280 ;
        RECT 1802.470 0.350 1807.150 4.280 ;
        RECT 1807.990 0.350 1812.670 4.280 ;
        RECT 1813.510 0.350 1818.190 4.280 ;
        RECT 1819.030 0.350 1823.710 4.280 ;
        RECT 1824.550 0.350 1829.230 4.280 ;
        RECT 1830.070 0.350 1834.750 4.280 ;
        RECT 1835.590 0.350 1840.270 4.280 ;
        RECT 1841.110 0.350 1845.790 4.280 ;
        RECT 1846.630 0.350 1851.310 4.280 ;
        RECT 1852.150 0.350 1856.830 4.280 ;
        RECT 1857.670 0.350 1862.350 4.280 ;
        RECT 1863.190 0.350 1867.870 4.280 ;
        RECT 1868.710 0.350 1873.390 4.280 ;
        RECT 1874.230 0.350 1878.910 4.280 ;
        RECT 1879.750 0.350 1884.430 4.280 ;
        RECT 1885.270 0.350 1889.950 4.280 ;
        RECT 1890.790 0.350 1895.470 4.280 ;
        RECT 1896.310 0.350 1900.990 4.280 ;
        RECT 1901.830 0.350 1906.510 4.280 ;
        RECT 1907.350 0.350 1912.030 4.280 ;
        RECT 1912.870 0.350 1917.550 4.280 ;
        RECT 1918.390 0.350 1923.070 4.280 ;
        RECT 1923.910 0.350 1928.590 4.280 ;
        RECT 1929.430 0.350 1934.110 4.280 ;
        RECT 1934.950 0.350 1939.630 4.280 ;
        RECT 1940.470 0.350 1945.150 4.280 ;
        RECT 1945.990 0.350 1950.670 4.280 ;
        RECT 1951.510 0.350 1956.190 4.280 ;
        RECT 1957.030 0.350 1961.710 4.280 ;
        RECT 1962.550 0.350 1967.230 4.280 ;
        RECT 1968.070 0.350 1972.750 4.280 ;
        RECT 1973.590 0.350 1978.270 4.280 ;
        RECT 1979.110 0.350 1983.790 4.280 ;
        RECT 1984.630 0.350 1989.310 4.280 ;
        RECT 1990.150 0.350 1994.830 4.280 ;
        RECT 1995.670 0.350 2000.350 4.280 ;
        RECT 2001.190 0.350 2005.870 4.280 ;
        RECT 2006.710 0.350 2011.390 4.280 ;
        RECT 2012.230 0.350 2016.910 4.280 ;
        RECT 2017.750 0.350 2022.430 4.280 ;
        RECT 2023.270 0.350 2027.950 4.280 ;
        RECT 2028.790 0.350 2033.470 4.280 ;
        RECT 2034.310 0.350 2038.990 4.280 ;
        RECT 2039.830 0.350 2044.510 4.280 ;
        RECT 2045.350 0.350 2050.030 4.280 ;
        RECT 2050.870 0.350 2055.550 4.280 ;
        RECT 2056.390 0.350 2061.070 4.280 ;
        RECT 2061.910 0.350 2066.590 4.280 ;
        RECT 2067.430 0.350 2072.110 4.280 ;
        RECT 2072.950 0.350 2077.630 4.280 ;
        RECT 2078.470 0.350 2083.150 4.280 ;
        RECT 2083.990 0.350 2088.670 4.280 ;
        RECT 2089.510 0.350 2094.190 4.280 ;
        RECT 2095.030 0.350 2099.710 4.280 ;
        RECT 2100.550 0.350 2105.230 4.280 ;
        RECT 2106.070 0.350 2110.750 4.280 ;
        RECT 2111.590 0.350 2116.270 4.280 ;
        RECT 2117.110 0.350 2121.790 4.280 ;
        RECT 2122.630 0.350 2127.310 4.280 ;
        RECT 2128.150 0.350 2132.830 4.280 ;
        RECT 2133.670 0.350 2138.350 4.280 ;
        RECT 2139.190 0.350 2143.870 4.280 ;
        RECT 2144.710 0.350 2149.390 4.280 ;
        RECT 2150.230 0.350 2154.910 4.280 ;
        RECT 2155.750 0.350 2160.430 4.280 ;
        RECT 2161.270 0.350 2165.950 4.280 ;
        RECT 2166.790 0.350 2171.470 4.280 ;
        RECT 2172.310 0.350 2176.990 4.280 ;
        RECT 2177.830 0.350 2182.510 4.280 ;
        RECT 2183.350 0.350 2188.030 4.280 ;
        RECT 2188.870 0.350 2193.550 4.280 ;
        RECT 2194.390 0.350 2199.070 4.280 ;
        RECT 2199.910 0.350 2204.590 4.280 ;
        RECT 2205.430 0.350 2210.110 4.280 ;
        RECT 2210.950 0.350 2215.630 4.280 ;
        RECT 2216.470 0.350 2221.150 4.280 ;
        RECT 2221.990 0.350 2226.670 4.280 ;
        RECT 2227.510 0.350 2232.190 4.280 ;
        RECT 2233.030 0.350 2237.710 4.280 ;
        RECT 2238.550 0.350 2243.230 4.280 ;
        RECT 2244.070 0.350 2248.750 4.280 ;
        RECT 2249.590 0.350 2254.270 4.280 ;
        RECT 2255.110 0.350 2259.790 4.280 ;
        RECT 2260.630 0.350 2265.310 4.280 ;
        RECT 2266.150 0.350 2270.830 4.280 ;
        RECT 2271.670 0.350 2276.350 4.280 ;
        RECT 2277.190 0.350 2281.870 4.280 ;
        RECT 2282.710 0.350 2287.390 4.280 ;
        RECT 2288.230 0.350 2292.910 4.280 ;
        RECT 2293.750 0.350 2298.430 4.280 ;
        RECT 2299.270 0.350 2303.950 4.280 ;
        RECT 2304.790 0.350 2309.470 4.280 ;
        RECT 2310.310 0.350 2314.990 4.280 ;
        RECT 2315.830 0.350 2320.510 4.280 ;
        RECT 2321.350 0.350 2326.030 4.280 ;
        RECT 2326.870 0.350 2331.550 4.280 ;
        RECT 2332.390 0.350 2337.070 4.280 ;
        RECT 2337.910 0.350 2342.590 4.280 ;
        RECT 2343.430 0.350 2348.110 4.280 ;
        RECT 2348.950 0.350 2353.630 4.280 ;
        RECT 2354.470 0.350 2359.150 4.280 ;
        RECT 2359.990 0.350 2364.670 4.280 ;
        RECT 2365.510 0.350 2370.190 4.280 ;
        RECT 2371.030 0.350 2375.710 4.280 ;
        RECT 2376.550 0.350 2381.230 4.280 ;
        RECT 2382.070 0.350 2386.750 4.280 ;
        RECT 2387.590 0.350 2392.270 4.280 ;
        RECT 2393.110 0.350 2397.790 4.280 ;
        RECT 2398.630 0.350 2403.310 4.280 ;
        RECT 2404.150 0.350 2408.830 4.280 ;
        RECT 2409.670 0.350 2414.350 4.280 ;
        RECT 2415.190 0.350 2419.870 4.280 ;
        RECT 2420.710 0.350 2425.390 4.280 ;
        RECT 2426.230 0.350 2430.910 4.280 ;
        RECT 2431.750 0.350 2436.430 4.280 ;
        RECT 2437.270 0.350 2441.950 4.280 ;
        RECT 2442.790 0.350 2447.470 4.280 ;
        RECT 2448.310 0.350 2452.990 4.280 ;
        RECT 2453.830 0.350 2458.510 4.280 ;
        RECT 2459.350 0.350 2464.030 4.280 ;
        RECT 2464.870 0.350 2469.550 4.280 ;
        RECT 2470.390 0.350 2475.070 4.280 ;
        RECT 2475.910 0.350 2480.590 4.280 ;
        RECT 2481.430 0.350 2486.110 4.280 ;
        RECT 2486.950 0.350 2491.630 4.280 ;
        RECT 2492.470 0.350 2497.150 4.280 ;
        RECT 2497.990 0.350 2502.670 4.280 ;
        RECT 2503.510 0.350 2508.190 4.280 ;
        RECT 2509.030 0.350 2513.710 4.280 ;
        RECT 2514.550 0.350 2519.230 4.280 ;
        RECT 2520.070 0.350 2524.750 4.280 ;
        RECT 2525.590 0.350 2530.270 4.280 ;
        RECT 2531.110 0.350 2535.790 4.280 ;
        RECT 2536.630 0.350 2541.310 4.280 ;
        RECT 2542.150 0.350 2546.830 4.280 ;
        RECT 2547.670 0.350 2552.350 4.280 ;
        RECT 2553.190 0.350 2557.870 4.280 ;
        RECT 2558.710 0.350 2563.390 4.280 ;
        RECT 2564.230 0.350 2568.910 4.280 ;
        RECT 2569.750 0.350 2574.430 4.280 ;
        RECT 2575.270 0.350 2579.950 4.280 ;
        RECT 2580.790 0.350 2585.470 4.280 ;
        RECT 2586.310 0.350 2590.990 4.280 ;
        RECT 2591.830 0.350 2596.510 4.280 ;
        RECT 2597.350 0.350 2602.030 4.280 ;
        RECT 2602.870 0.350 2607.550 4.280 ;
        RECT 2608.390 0.350 2613.070 4.280 ;
        RECT 2613.910 0.350 2618.590 4.280 ;
        RECT 2619.430 0.350 2624.110 4.280 ;
        RECT 2624.950 0.350 2629.630 4.280 ;
        RECT 2630.470 0.350 2635.150 4.280 ;
        RECT 2635.990 0.350 2640.670 4.280 ;
        RECT 2641.510 0.350 2646.190 4.280 ;
        RECT 2647.030 0.350 2651.710 4.280 ;
        RECT 2652.550 0.350 2657.230 4.280 ;
        RECT 2658.070 0.350 2662.750 4.280 ;
        RECT 2663.590 0.350 2668.270 4.280 ;
        RECT 2669.110 0.350 2673.790 4.280 ;
        RECT 2674.630 0.350 2679.310 4.280 ;
        RECT 2680.150 0.350 2684.830 4.280 ;
        RECT 2685.670 0.350 2690.350 4.280 ;
        RECT 2691.190 0.350 2695.870 4.280 ;
        RECT 2696.710 0.350 2701.390 4.280 ;
        RECT 2702.230 0.350 2706.910 4.280 ;
        RECT 2707.750 0.350 2712.430 4.280 ;
        RECT 2713.270 0.350 2717.950 4.280 ;
        RECT 2718.790 0.350 2723.470 4.280 ;
        RECT 2724.310 0.350 2728.990 4.280 ;
        RECT 2729.830 0.350 2734.510 4.280 ;
        RECT 2735.350 0.350 2740.030 4.280 ;
        RECT 2740.870 0.350 2745.550 4.280 ;
        RECT 2746.390 0.350 2751.070 4.280 ;
        RECT 2751.910 0.350 2756.590 4.280 ;
        RECT 2757.430 0.350 2762.110 4.280 ;
        RECT 2762.950 0.350 2767.630 4.280 ;
        RECT 2768.470 0.350 2773.150 4.280 ;
        RECT 2773.990 0.350 2778.670 4.280 ;
        RECT 2779.510 0.350 2784.190 4.280 ;
        RECT 2785.030 0.350 2789.710 4.280 ;
        RECT 2790.550 0.350 2795.230 4.280 ;
        RECT 2796.070 0.350 2800.750 4.280 ;
        RECT 2801.590 0.350 2806.270 4.280 ;
        RECT 2807.110 0.350 2811.790 4.280 ;
        RECT 2812.630 0.350 2817.310 4.280 ;
        RECT 2818.150 0.350 2912.170 4.280 ;
      LAYER met3 ;
        RECT 3.990 2438.160 2916.000 2488.965 ;
        RECT 4.400 2436.760 2915.600 2438.160 ;
        RECT 3.990 2334.800 2916.000 2436.760 ;
        RECT 4.400 2333.400 2915.600 2334.800 ;
        RECT 3.990 2231.440 2916.000 2333.400 ;
        RECT 4.400 2230.040 2915.600 2231.440 ;
        RECT 3.990 2128.080 2916.000 2230.040 ;
        RECT 4.400 2126.680 2915.600 2128.080 ;
        RECT 3.990 2024.720 2916.000 2126.680 ;
        RECT 4.400 2023.320 2915.600 2024.720 ;
        RECT 3.990 1921.360 2916.000 2023.320 ;
        RECT 4.400 1919.960 2915.600 1921.360 ;
        RECT 3.990 1818.000 2916.000 1919.960 ;
        RECT 4.400 1816.600 2915.600 1818.000 ;
        RECT 3.990 1714.640 2916.000 1816.600 ;
        RECT 4.400 1713.240 2915.600 1714.640 ;
        RECT 3.990 1611.280 2916.000 1713.240 ;
        RECT 4.400 1609.880 2915.600 1611.280 ;
        RECT 3.990 1507.920 2916.000 1609.880 ;
        RECT 4.400 1506.520 2915.600 1507.920 ;
        RECT 3.990 1404.560 2916.000 1506.520 ;
        RECT 4.400 1403.160 2915.600 1404.560 ;
        RECT 3.990 1301.200 2916.000 1403.160 ;
        RECT 4.400 1299.800 2915.600 1301.200 ;
        RECT 3.990 1197.840 2916.000 1299.800 ;
        RECT 4.400 1196.440 2915.600 1197.840 ;
        RECT 3.990 1094.480 2916.000 1196.440 ;
        RECT 4.400 1093.080 2915.600 1094.480 ;
        RECT 3.990 991.120 2916.000 1093.080 ;
        RECT 4.400 989.720 2915.600 991.120 ;
        RECT 3.990 887.760 2916.000 989.720 ;
        RECT 4.400 886.360 2915.600 887.760 ;
        RECT 3.990 784.400 2916.000 886.360 ;
        RECT 4.400 783.000 2915.600 784.400 ;
        RECT 3.990 681.040 2916.000 783.000 ;
        RECT 4.400 679.640 2915.600 681.040 ;
        RECT 3.990 577.680 2916.000 679.640 ;
        RECT 4.400 576.280 2915.600 577.680 ;
        RECT 3.990 474.320 2916.000 576.280 ;
        RECT 4.400 472.920 2915.600 474.320 ;
        RECT 3.990 370.960 2916.000 472.920 ;
        RECT 4.400 369.560 2915.600 370.960 ;
        RECT 3.990 267.600 2916.000 369.560 ;
        RECT 4.400 266.200 2915.600 267.600 ;
        RECT 3.990 164.240 2916.000 266.200 ;
        RECT 4.400 162.840 2915.600 164.240 ;
        RECT 3.990 60.880 2916.000 162.840 ;
        RECT 4.400 59.480 2915.600 60.880 ;
        RECT 3.990 10.715 2916.000 59.480 ;
      LAYER met4 ;
        RECT 104.255 40.975 174.240 1380.225 ;
        RECT 176.640 40.975 177.540 1380.225 ;
        RECT 179.940 40.975 327.840 1380.225 ;
        RECT 330.240 40.975 331.140 1380.225 ;
        RECT 333.540 40.975 481.440 1380.225 ;
        RECT 483.840 40.975 484.740 1380.225 ;
        RECT 487.140 40.975 635.040 1380.225 ;
        RECT 637.440 40.975 638.340 1380.225 ;
        RECT 640.740 40.975 788.640 1380.225 ;
        RECT 791.040 40.975 791.940 1380.225 ;
        RECT 794.340 40.975 942.240 1380.225 ;
        RECT 944.640 40.975 945.540 1380.225 ;
        RECT 947.940 40.975 1095.840 1380.225 ;
        RECT 1098.240 40.975 1099.140 1380.225 ;
        RECT 1101.540 40.975 1249.440 1380.225 ;
        RECT 1251.840 40.975 1252.740 1380.225 ;
        RECT 1255.140 40.975 1403.040 1380.225 ;
        RECT 1405.440 40.975 1406.340 1380.225 ;
        RECT 1408.740 40.975 1556.640 1380.225 ;
        RECT 1559.040 40.975 1559.940 1380.225 ;
        RECT 1562.340 40.975 1710.240 1380.225 ;
        RECT 1712.640 40.975 1713.540 1380.225 ;
        RECT 1715.940 40.975 1863.840 1380.225 ;
        RECT 1866.240 40.975 1867.140 1380.225 ;
        RECT 1869.540 40.975 2017.440 1380.225 ;
        RECT 2019.840 40.975 2020.740 1380.225 ;
        RECT 2023.140 40.975 2088.105 1380.225 ;
  END
END senseedge_top
END LIBRARY

